VERSION 5.7 ;
  NOWIREEXTENSIONATPIN ON ;
  DIVIDERCHAR "/" ;
  BUSBITCHARS "[]" ;
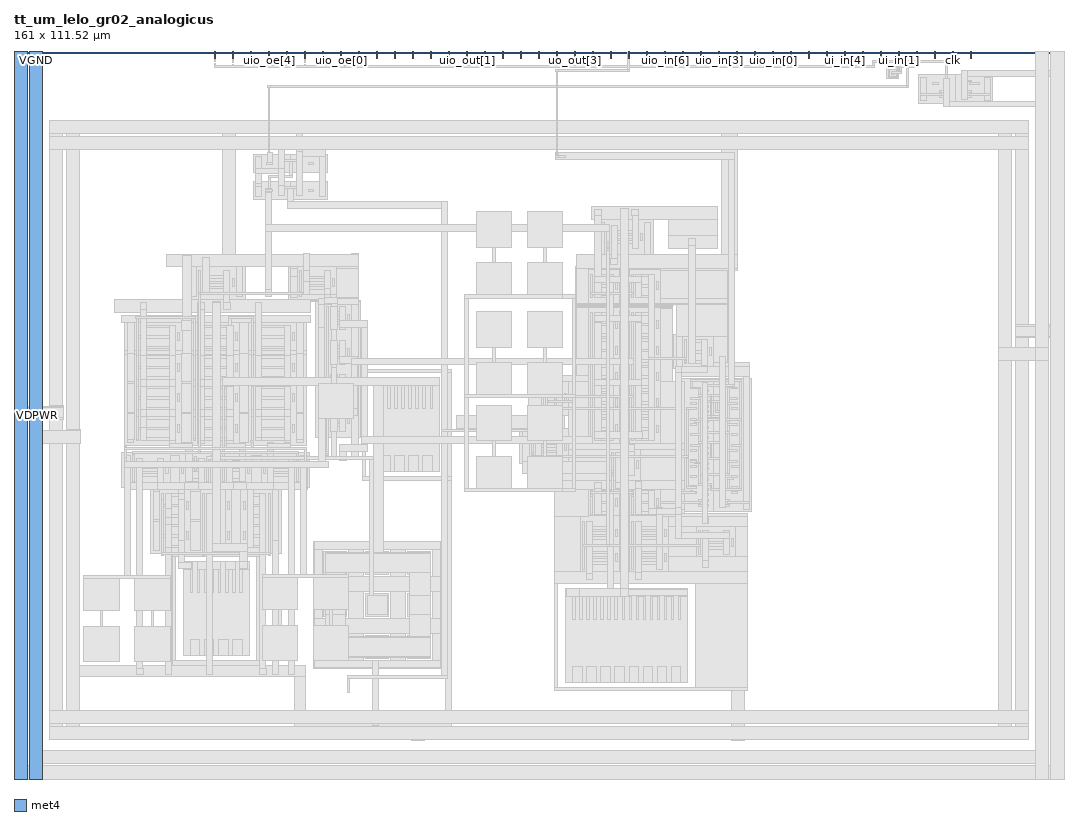
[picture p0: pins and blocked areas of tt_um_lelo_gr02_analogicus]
MACRO tt_um_lelo_gr02_analogicus
  CLASS BLOCK ;
  FOREIGN tt_um_lelo_gr02_analogicus ;
  ORIGIN 0.000 0.000 ;
  SIZE 161.000 BY 111.520 ;
  PIN uo_out[7]
    DIRECTION OUTPUT ;
    USE SIGNAL ;
    PORT
      LAYER met4 ;
        RECT 74.830 110.520 75.130 111.520 ;
    END
  END uo_out[7]
  PIN uo_out[6]
    DIRECTION OUTPUT ;
    USE SIGNAL ;
    PORT
      LAYER met4 ;
        RECT 77.590 110.520 77.890 111.520 ;
    END
  END uo_out[6]
  PIN uo_out[5]
    DIRECTION OUTPUT ;
    USE SIGNAL ;
    PORT
      LAYER met4 ;
        RECT 80.350 110.520 80.650 111.520 ;
    END
  END uo_out[5]
  PIN uo_out[4]
    DIRECTION OUTPUT ;
    USE SIGNAL ;
    PORT
      LAYER met4 ;
        RECT 83.110 110.520 83.410 111.520 ;
    END
  END uo_out[4]
  PIN uo_out[3]
    DIRECTION OUTPUT ;
    USE SIGNAL ;
    PORT
      LAYER met4 ;
        RECT 85.870 110.520 86.170 111.520 ;
    END
  END uo_out[3]
  PIN uo_out[2]
    DIRECTION OUTPUT ;
    USE SIGNAL ;
    PORT
      LAYER met4 ;
        RECT 88.630 110.520 88.930 111.520 ;
    END
  END uo_out[2]
  PIN uo_out[1]
    DIRECTION OUTPUT ;
    USE SIGNAL ;
    PORT
      LAYER met4 ;
        RECT 91.390 110.520 91.690 111.520 ;
    END
  END uo_out[1]
  PIN uo_out[0]
    DIRECTION OUTPUT ;
    USE SIGNAL ;
    ANTENNAGATEAREA 0.288000 ;
    ANTENNADIFFAREA 0.936000 ;
    PORT
      LAYER met4 ;
        RECT 94.150 110.520 94.450 111.520 ;
    END
  END uo_out[0]
  PIN uio_out[7]
    DIRECTION OUTPUT ;
    USE SIGNAL ;
    PORT
      LAYER met4 ;
        RECT 52.750 110.520 53.050 111.520 ;
    END
  END uio_out[7]
  PIN uio_out[6]
    DIRECTION OUTPUT ;
    USE SIGNAL ;
    PORT
      LAYER met4 ;
        RECT 55.510 110.520 55.810 111.520 ;
    END
  END uio_out[6]
  PIN uio_out[5]
    DIRECTION OUTPUT ;
    USE SIGNAL ;
    PORT
      LAYER met4 ;
        RECT 58.270 110.520 58.570 111.520 ;
    END
  END uio_out[5]
  PIN uio_out[4]
    DIRECTION OUTPUT ;
    USE SIGNAL ;
    PORT
      LAYER met4 ;
        RECT 61.030 110.520 61.330 111.520 ;
    END
  END uio_out[4]
  PIN uio_out[3]
    DIRECTION OUTPUT ;
    USE SIGNAL ;
    PORT
      LAYER met4 ;
        RECT 63.790 110.520 64.090 111.520 ;
    END
  END uio_out[3]
  PIN uio_out[2]
    DIRECTION OUTPUT ;
    USE SIGNAL ;
    PORT
      LAYER met4 ;
        RECT 66.550 110.520 66.850 111.520 ;
    END
  END uio_out[2]
  PIN uio_out[1]
    DIRECTION OUTPUT ;
    USE SIGNAL ;
    PORT
      LAYER met4 ;
        RECT 69.310 110.520 69.610 111.520 ;
    END
  END uio_out[1]
  PIN uio_out[0]
    DIRECTION OUTPUT ;
    USE SIGNAL ;
    PORT
      LAYER met4 ;
        RECT 72.070 110.520 72.370 111.520 ;
    END
  END uio_out[0]
  PIN uio_oe[7]
    DIRECTION OUTPUT ;
    USE SIGNAL ;
    PORT
      LAYER met4 ;
        RECT 30.670 110.520 30.970 111.520 ;
    END
  END uio_oe[7]
  PIN uio_oe[6]
    DIRECTION OUTPUT ;
    USE SIGNAL ;
    PORT
      LAYER met4 ;
        RECT 33.430 110.520 33.730 111.520 ;
    END
  END uio_oe[6]
  PIN uio_oe[5]
    DIRECTION OUTPUT ;
    USE SIGNAL ;
    PORT
      LAYER met4 ;
        RECT 36.190 110.520 36.490 111.520 ;
    END
  END uio_oe[5]
  PIN uio_oe[4]
    DIRECTION OUTPUT ;
    USE SIGNAL ;
    PORT
      LAYER met4 ;
        RECT 38.950 110.520 39.250 111.520 ;
    END
  END uio_oe[4]
  PIN uio_oe[3]
    DIRECTION OUTPUT ;
    USE SIGNAL ;
    PORT
      LAYER met4 ;
        RECT 41.710 110.520 42.010 111.520 ;
    END
  END uio_oe[3]
  PIN uio_oe[2]
    DIRECTION OUTPUT ;
    USE SIGNAL ;
    PORT
      LAYER met4 ;
        RECT 44.470 110.520 44.770 111.520 ;
    END
  END uio_oe[2]
  PIN uio_oe[1]
    DIRECTION OUTPUT ;
    USE SIGNAL ;
    PORT
      LAYER met4 ;
        RECT 47.230 110.520 47.530 111.520 ;
    END
  END uio_oe[1]
  PIN uio_oe[0]
    DIRECTION OUTPUT ;
    USE SIGNAL ;
    PORT
      LAYER met4 ;
        RECT 49.990 110.520 50.290 111.520 ;
    END
  END uio_oe[0]
  PIN VDPWR
    DIRECTION INOUT ;
    USE POWER ;
    PORT
      LAYER met4 ;
        RECT 0.000 0.000 2.000 111.520 ;
    END
  END VDPWR
  PIN VGND
    DIRECTION INOUT ;
    USE GROUND ;
    PORT
      LAYER met4 ;
        RECT 2.400 0.000 4.400 111.520 ;
    END
  END VGND
  PIN ui_in[7]
    DIRECTION INPUT ;
    USE SIGNAL ;
    PORT
      LAYER met4 ;
        RECT 118.990 110.520 119.290 111.520 ;
    END
  END ui_in[7]
  PIN ui_in[6]
    DIRECTION INPUT ;
    USE SIGNAL ;
    PORT
      LAYER met4 ;
        RECT 121.750 110.520 122.050 111.520 ;
    END
  END ui_in[6]
  PIN ui_in[5]
    DIRECTION INPUT ;
    USE SIGNAL ;
    PORT
      LAYER met4 ;
        RECT 124.510 110.520 124.810 111.520 ;
    END
  END ui_in[5]
  PIN ui_in[4]
    DIRECTION INPUT ;
    USE SIGNAL ;
    PORT
      LAYER met4 ;
        RECT 127.270 110.520 127.570 111.520 ;
    END
  END ui_in[4]
  PIN ui_in[3]
    DIRECTION INPUT ;
    USE SIGNAL ;
    PORT
      LAYER met4 ;
        RECT 130.030 110.520 130.330 111.520 ;
    END
  END ui_in[3]
  PIN ui_in[2]
    DIRECTION INPUT ;
    USE SIGNAL ;
    PORT
      LAYER met4 ;
        RECT 132.790 110.520 133.090 111.520 ;
    END
  END ui_in[2]
  PIN ui_in[1]
    DIRECTION INPUT ;
    USE SIGNAL ;
    PORT
      LAYER met4 ;
        RECT 135.550 110.520 135.850 111.520 ;
    END
  END ui_in[1]
  PIN ui_in[0]
    DIRECTION INPUT ;
    USE SIGNAL ;
    ANTENNAGATEAREA 0.490500 ;
    ANTENNADIFFAREA 0.202500 ;
    PORT
      LAYER met4 ;
        RECT 138.310 110.520 138.610 111.520 ;
    END
  END ui_in[0]
  PIN uio_in[7]
    DIRECTION INPUT ;
    USE SIGNAL ;
    PORT
      LAYER met4 ;
        RECT 96.910 110.520 97.210 111.520 ;
    END
  END uio_in[7]
  PIN uio_in[6]
    DIRECTION INPUT ;
    USE SIGNAL ;
    PORT
      LAYER met4 ;
        RECT 99.670 110.520 99.970 111.520 ;
    END
  END uio_in[6]
  PIN uio_in[5]
    DIRECTION INPUT ;
    USE SIGNAL ;
    PORT
      LAYER met4 ;
        RECT 102.430 110.520 102.730 111.520 ;
    END
  END uio_in[5]
  PIN uio_in[4]
    DIRECTION INPUT ;
    USE SIGNAL ;
    PORT
      LAYER met4 ;
        RECT 105.190 110.520 105.490 111.520 ;
    END
  END uio_in[4]
  PIN uio_in[3]
    DIRECTION INPUT ;
    USE SIGNAL ;
    PORT
      LAYER met4 ;
        RECT 107.950 110.520 108.250 111.520 ;
    END
  END uio_in[3]
  PIN uio_in[2]
    DIRECTION INPUT ;
    USE SIGNAL ;
    PORT
      LAYER met4 ;
        RECT 110.710 110.520 111.010 111.520 ;
    END
  END uio_in[2]
  PIN uio_in[1]
    DIRECTION INPUT ;
    USE SIGNAL ;
    PORT
      LAYER met4 ;
        RECT 113.470 110.520 113.770 111.520 ;
    END
  END uio_in[1]
  PIN uio_in[0]
    DIRECTION INPUT ;
    USE SIGNAL ;
    PORT
      LAYER met4 ;
        RECT 116.230 110.520 116.530 111.520 ;
    END
  END uio_in[0]
  PIN ena
    DIRECTION INPUT ;
    USE SIGNAL ;
    PORT
      LAYER met4 ;
        RECT 146.590 110.520 146.890 111.520 ;
    END
  END ena
  PIN rst_n
    DIRECTION INPUT ;
    USE SIGNAL ;
    PORT
      LAYER met4 ;
        RECT 141.070 110.520 141.370 111.520 ;
    END
  END rst_n
  PIN clk
    DIRECTION INPUT ;
    USE SIGNAL ;
    PORT
      LAYER met4 ;
        RECT 143.830 110.520 144.130 111.520 ;
    END
  END clk
  OBS
      LAYER pwell ;
        RECT 133.855 107.375 135.685 109.205 ;
        RECT 138.680 103.630 144.380 108.030 ;
      LAYER nwell ;
        RECT 144.380 103.630 150.080 108.030 ;
      LAYER pwell ;
        RECT 36.690 93.010 42.390 95.810 ;
      LAYER nwell ;
        RECT 42.390 93.010 48.090 95.810 ;
      LAYER pwell ;
        RECT 36.690 88.860 42.390 91.660 ;
      LAYER nwell ;
        RECT 42.390 88.860 48.090 91.660 ;
        RECT 89.205 80.475 98.085 85.755 ;
        RECT 26.600 73.520 35.480 78.800 ;
        RECT 42.020 74.295 50.900 78.740 ;
        RECT 86.130 78.105 101.155 78.625 ;
        RECT 42.020 73.460 50.910 74.295 ;
        RECT 42.025 73.320 50.910 73.460 ;
        RECT 42.025 73.240 53.190 73.320 ;
        RECT 17.000 65.750 44.785 70.430 ;
        RECT 16.995 65.150 44.785 65.750 ;
        RECT 16.995 51.130 44.780 65.150 ;
        RECT 46.230 52.395 53.190 73.240 ;
        RECT 86.130 72.575 101.165 78.105 ;
        RECT 86.130 72.570 101.155 72.575 ;
      LAYER pwell ;
        RECT 86.690 72.320 94.290 72.325 ;
        RECT 23.985 50.045 37.840 50.050 ;
        RECT 16.455 50.040 37.840 50.045 ;
        RECT 16.455 44.770 45.370 50.040 ;
        RECT 55.150 47.140 65.230 61.540 ;
        RECT 79.505 55.795 86.465 61.075 ;
        RECT 77.585 48.400 86.465 53.680 ;
        RECT 86.690 51.045 100.540 72.320 ;
      LAYER nwell ;
        RECT 101.115 62.875 108.715 68.155 ;
      LAYER pwell ;
        RECT 92.940 51.040 100.540 51.045 ;
        RECT 89.895 45.645 97.495 50.925 ;
        RECT 16.455 44.765 25.335 44.770 ;
        RECT 36.490 44.760 45.370 44.770 ;
        RECT 27.145 44.595 34.745 44.600 ;
        RECT 20.885 34.645 40.995 44.595 ;
        RECT 86.690 40.360 100.540 45.030 ;
        RECT 101.625 40.955 107.325 61.355 ;
      LAYER nwell ;
        RECT 107.325 40.955 113.025 61.355 ;
      LAYER pwell ;
        RECT 20.885 34.640 28.485 34.645 ;
        RECT 33.395 34.640 40.995 34.645 ;
        RECT 45.900 35.705 65.480 36.470 ;
        RECT 25.975 18.950 36.055 33.350 ;
        RECT 45.900 30.535 46.665 35.705 ;
        RECT 51.835 30.535 53.105 35.705 ;
        RECT 58.275 30.535 59.545 35.705 ;
        RECT 64.715 30.535 65.480 35.705 ;
        RECT 85.410 31.300 101.820 40.360 ;
        RECT 103.200 33.605 112.080 38.885 ;
        RECT 45.900 29.265 65.480 30.535 ;
        RECT 45.900 24.095 46.665 29.265 ;
        RECT 51.835 24.095 53.105 29.265 ;
        RECT 58.275 24.095 59.545 29.265 ;
        RECT 64.715 24.095 65.480 29.265 ;
        RECT 45.900 22.825 65.480 24.095 ;
        RECT 45.900 17.655 46.665 22.825 ;
        RECT 51.835 17.655 53.105 22.825 ;
        RECT 58.275 17.655 59.545 22.825 ;
        RECT 64.715 17.655 65.480 22.825 ;
        RECT 45.900 16.890 65.480 17.655 ;
        RECT 84.590 14.830 103.310 29.230 ;
      LAYER li1 ;
        RECT 134.035 108.855 135.505 109.025 ;
        RECT 134.035 107.725 134.205 108.855 ;
        RECT 134.525 108.125 135.015 108.455 ;
        RECT 135.335 107.725 135.505 108.855 ;
        RECT 134.035 107.555 135.505 107.725 ;
        RECT 138.980 105.180 139.880 107.630 ;
        RECT 142.790 107.180 143.090 108.350 ;
        RECT 142.580 106.880 143.480 107.180 ;
        RECT 145.280 106.880 146.780 107.180 ;
        RECT 146.480 106.780 146.780 106.880 ;
        RECT 140.780 106.480 141.680 106.780 ;
        RECT 146.480 106.480 147.980 106.780 ;
        RECT 142.580 106.380 143.420 106.400 ;
        RECT 145.280 106.380 146.120 106.400 ;
        RECT 142.580 106.080 143.480 106.380 ;
        RECT 145.280 106.080 146.180 106.380 ;
        RECT 142.580 105.580 143.420 105.600 ;
        RECT 145.280 105.580 146.120 105.600 ;
        RECT 141.980 105.280 143.480 105.580 ;
        RECT 145.280 105.280 146.780 105.580 ;
        RECT 141.980 105.180 142.280 105.280 ;
        RECT 138.980 104.880 142.280 105.180 ;
        RECT 138.980 104.030 139.880 104.880 ;
        RECT 141.980 104.780 142.280 104.880 ;
        RECT 146.480 105.180 146.780 105.280 ;
        RECT 148.880 105.180 149.780 107.630 ;
        RECT 146.480 104.880 149.780 105.180 ;
        RECT 142.580 104.780 143.420 104.800 ;
        RECT 145.280 104.780 146.120 104.800 ;
        RECT 146.480 104.780 146.780 104.880 ;
        RECT 141.980 104.480 143.480 104.780 ;
        RECT 145.280 104.480 146.780 104.780 ;
        RECT 148.880 104.030 149.780 104.880 ;
        RECT 32.000 80.500 34.000 101.000 ;
        RECT 46.890 96.500 47.795 96.505 ;
        RECT 38.805 95.570 39.685 96.005 ;
        RECT 36.990 93.600 37.890 95.410 ;
        RECT 38.795 94.560 39.690 95.570 ;
        RECT 43.290 95.500 47.795 96.500 ;
        RECT 43.290 95.490 44.170 95.500 ;
        RECT 46.890 95.410 47.795 95.500 ;
        RECT 42.280 94.960 42.650 94.995 ;
        RECT 40.590 94.660 44.190 94.960 ;
        RECT 38.790 94.260 39.690 94.560 ;
        RECT 40.590 94.160 41.430 94.180 ;
        RECT 40.590 93.860 41.490 94.160 ;
        RECT 36.990 92.800 41.400 93.600 ;
        RECT 36.990 91.260 37.890 92.800 ;
        RECT 42.280 92.610 42.650 94.660 ;
        RECT 45.090 94.260 45.990 94.560 ;
        RECT 43.290 94.160 44.130 94.180 ;
        RECT 43.290 93.860 44.190 94.160 ;
        RECT 38.965 92.240 42.650 92.610 ;
        RECT 36.990 90.870 37.905 91.260 ;
        RECT 36.990 90.860 37.900 90.870 ;
        RECT 36.990 89.260 37.890 90.860 ;
        RECT 38.965 90.500 39.335 92.240 ;
        RECT 40.590 90.510 44.190 90.810 ;
        RECT 38.500 90.410 39.500 90.500 ;
        RECT 38.500 90.110 39.690 90.410 ;
        RECT 38.500 89.000 39.500 90.110 ;
        RECT 40.590 90.010 41.430 90.030 ;
        RECT 40.590 89.710 41.490 90.010 ;
        RECT 41.900 88.500 42.900 90.510 ;
        RECT 45.090 90.110 45.990 90.410 ;
        RECT 43.290 90.010 44.130 90.030 ;
        RECT 43.290 89.710 44.190 90.010 ;
        RECT 46.890 89.260 47.790 95.410 ;
        RECT 41.900 87.500 66.500 88.500 ;
        RECT 88.610 85.840 107.900 87.840 ;
        RECT 51.790 80.500 52.750 80.520 ;
        RECT 23.440 78.540 52.750 80.500 ;
        RECT 89.645 80.400 90.605 85.315 ;
        RECT 91.565 83.715 95.085 84.115 ;
        RECT 90.925 82.515 91.245 83.715 ;
        RECT 92.205 82.915 95.725 83.315 ;
        RECT 96.045 82.515 96.365 83.715 ;
        RECT 91.565 82.115 95.085 82.515 ;
        RECT 96.685 80.400 97.645 85.315 ;
        RECT 100.400 83.330 107.900 85.840 ;
        RECT 100.400 81.330 107.915 83.330 ;
        RECT 101.555 80.400 108.275 80.405 ;
        RECT 108.500 80.400 111.000 101.000 ;
        RECT 27.040 73.960 28.000 78.540 ;
        RECT 28.960 76.760 32.480 77.160 ;
        RECT 28.320 75.560 28.640 76.760 ;
        RECT 29.600 75.960 33.120 76.360 ;
        RECT 33.440 75.560 33.760 76.760 ;
        RECT 28.960 75.160 32.480 75.560 ;
        RECT 34.080 73.960 35.040 78.540 ;
        RECT 42.465 78.300 43.425 78.540 ;
        RECT 49.505 78.300 52.750 78.540 ;
        RECT 42.460 77.095 43.425 78.300 ;
        RECT 42.460 73.900 43.420 77.095 ;
        RECT 44.380 76.700 47.900 77.100 ;
        RECT 43.740 75.500 44.060 76.700 ;
        RECT 45.020 75.900 48.540 76.300 ;
        RECT 48.860 75.500 49.180 76.700 ;
        RECT 44.380 75.100 47.900 75.500 ;
        RECT 49.500 73.900 52.750 78.300 ;
        RECT 49.505 73.730 52.750 73.900 ;
        RECT 86.310 78.275 111.000 80.400 ;
        RECT 15.430 71.540 45.410 73.520 ;
        RECT 46.670 72.770 52.760 73.730 ;
        RECT 86.310 72.920 88.090 78.275 ;
        RECT 89.050 77.010 91.290 77.410 ;
        RECT 88.410 75.010 88.730 76.210 ;
        RECT 89.690 75.410 91.930 75.810 ;
        RECT 92.250 75.010 92.570 76.210 ;
        RECT 89.050 73.810 91.290 74.210 ;
        RECT 92.890 72.920 94.340 78.275 ;
        RECT 99.140 78.000 111.000 78.275 ;
        RECT 95.300 77.010 97.540 77.410 ;
        RECT 94.660 75.010 94.980 76.210 ;
        RECT 95.940 75.410 98.180 75.810 ;
        RECT 98.500 75.010 98.820 76.210 ;
        RECT 95.300 73.810 97.540 74.210 ;
        RECT 99.140 73.745 109.400 78.000 ;
        RECT 99.125 72.920 109.400 73.745 ;
        RECT 16.440 70.040 45.400 71.000 ;
        RECT 17.440 65.310 18.400 70.040 ;
        RECT 19.360 69.190 24.160 69.590 ;
        RECT 18.720 67.980 19.040 68.390 ;
        RECT 20.000 67.980 24.800 67.990 ;
        RECT 18.720 67.590 24.800 67.980 ;
        RECT 18.720 67.580 20.720 67.590 ;
        RECT 18.720 67.190 19.040 67.580 ;
        RECT 25.120 67.190 25.440 68.390 ;
        RECT 19.360 65.990 24.160 66.390 ;
        RECT 25.760 65.310 27.215 70.040 ;
        RECT 28.175 69.190 32.975 69.590 ;
        RECT 27.535 67.190 27.855 68.390 ;
        RECT 28.815 67.590 33.615 67.990 ;
        RECT 33.935 67.190 34.255 68.390 ;
        RECT 28.175 65.990 32.975 66.390 ;
        RECT 34.575 65.310 36.025 70.040 ;
        RECT 36.985 69.190 41.785 69.590 ;
        RECT 36.345 67.190 36.665 68.390 ;
        RECT 37.625 67.590 42.425 67.990 ;
        RECT 42.745 67.190 43.065 68.390 ;
        RECT 36.985 65.990 41.785 66.390 ;
        RECT 43.385 65.310 44.345 70.040 ;
        RECT 46.670 69.170 47.630 72.770 ;
        RECT 48.590 71.280 50.190 71.680 ;
        RECT 47.950 70.080 48.270 71.280 ;
        RECT 49.230 70.480 50.830 70.880 ;
        RECT 51.150 70.080 51.470 71.280 ;
        RECT 48.590 69.680 50.190 70.080 ;
        RECT 17.435 60.910 18.400 65.310 ;
        RECT 19.355 64.510 24.155 64.910 ;
        RECT 18.715 63.310 19.035 63.710 ;
        RECT 18.715 62.910 24.795 63.310 ;
        RECT 18.715 62.510 19.035 62.910 ;
        RECT 25.115 62.510 25.435 63.710 ;
        RECT 19.355 61.310 24.155 61.710 ;
        RECT 25.755 60.910 27.215 65.310 ;
        RECT 28.170 64.510 32.970 64.910 ;
        RECT 27.530 62.510 27.850 63.710 ;
        RECT 28.810 62.910 33.610 63.310 ;
        RECT 33.930 62.510 34.250 63.710 ;
        RECT 28.170 61.310 32.970 61.710 ;
        RECT 34.570 60.910 36.025 65.310 ;
        RECT 36.980 64.510 41.780 64.910 ;
        RECT 36.340 62.510 36.660 63.710 ;
        RECT 37.620 62.910 42.420 63.310 ;
        RECT 42.740 62.510 43.060 63.710 ;
        RECT 36.980 61.310 41.780 61.710 ;
        RECT 43.380 60.910 44.345 65.310 ;
        RECT 17.440 60.640 18.400 60.910 ;
        RECT 25.760 60.640 27.215 60.910 ;
        RECT 34.575 60.640 36.025 60.910 ;
        RECT 43.385 60.640 44.345 60.910 ;
        RECT 17.435 56.240 18.400 60.640 ;
        RECT 19.355 59.840 24.155 60.240 ;
        RECT 18.715 58.640 19.035 59.040 ;
        RECT 18.715 58.240 24.795 58.640 ;
        RECT 18.715 57.840 19.035 58.240 ;
        RECT 25.115 57.840 25.435 59.040 ;
        RECT 19.355 56.640 24.155 57.040 ;
        RECT 25.755 56.240 27.215 60.640 ;
        RECT 28.170 59.840 32.970 60.240 ;
        RECT 27.530 57.840 27.850 59.040 ;
        RECT 28.810 58.240 33.610 58.640 ;
        RECT 33.930 57.840 34.250 59.040 ;
        RECT 28.170 56.640 32.970 57.040 ;
        RECT 34.570 56.240 36.025 60.640 ;
        RECT 36.980 59.840 41.780 60.240 ;
        RECT 36.340 57.840 36.660 59.040 ;
        RECT 37.620 58.240 42.420 58.640 ;
        RECT 42.740 57.840 43.060 59.040 ;
        RECT 36.980 56.640 41.780 57.040 ;
        RECT 43.380 56.240 44.345 60.640 ;
        RECT 17.440 55.970 18.400 56.240 ;
        RECT 25.760 55.970 27.215 56.240 ;
        RECT 34.575 55.970 36.025 56.240 ;
        RECT 43.385 55.970 44.345 56.240 ;
        RECT 17.435 52.020 18.400 55.970 ;
        RECT 19.355 55.170 24.155 55.570 ;
        RECT 18.715 53.970 19.035 54.370 ;
        RECT 18.715 53.570 24.795 53.970 ;
        RECT 18.715 53.170 19.035 53.570 ;
        RECT 25.115 53.170 25.435 54.370 ;
        RECT 17.435 51.570 18.395 52.020 ;
        RECT 19.355 51.970 24.155 52.370 ;
        RECT 25.755 51.570 27.215 55.970 ;
        RECT 28.170 55.170 32.970 55.570 ;
        RECT 27.530 53.170 27.850 54.370 ;
        RECT 28.810 53.570 33.610 53.970 ;
        RECT 33.930 53.170 34.250 54.370 ;
        RECT 28.170 51.970 32.970 52.370 ;
        RECT 34.570 51.570 36.025 55.970 ;
        RECT 36.980 55.170 41.780 55.570 ;
        RECT 36.340 53.170 36.660 54.370 ;
        RECT 37.620 53.570 42.420 53.970 ;
        RECT 42.740 53.170 43.060 54.370 ;
        RECT 36.980 51.970 41.780 52.370 ;
        RECT 43.380 52.020 44.345 55.970 ;
        RECT 46.660 54.765 47.645 69.170 ;
        RECT 48.590 66.015 50.190 66.415 ;
        RECT 47.950 64.815 48.270 66.015 ;
        RECT 49.230 65.215 50.830 65.615 ;
        RECT 51.150 64.815 51.470 66.015 ;
        RECT 48.590 64.415 50.190 64.815 ;
        RECT 48.590 60.820 50.190 61.220 ;
        RECT 47.950 59.620 48.270 60.820 ;
        RECT 49.230 60.020 50.830 60.420 ;
        RECT 51.150 59.620 51.470 60.820 ;
        RECT 48.590 59.220 50.190 59.620 ;
        RECT 48.590 55.635 50.190 56.035 ;
        RECT 43.380 51.570 44.340 52.020 ;
        RECT 24.425 49.605 25.385 49.610 ;
        RECT 16.895 45.400 17.870 49.605 ;
        RECT 18.815 48.005 22.335 48.405 ;
        RECT 18.175 46.805 18.495 48.005 ;
        RECT 19.455 47.205 22.975 47.605 ;
        RECT 23.295 46.805 23.615 48.005 ;
        RECT 18.815 46.405 22.335 46.805 ;
        RECT 23.935 45.400 25.385 49.605 ;
        RECT 26.985 48.810 29.225 49.210 ;
        RECT 25.705 46.810 26.025 48.010 ;
        RECT 26.345 47.210 28.585 47.610 ;
        RECT 29.545 46.810 29.865 48.010 ;
        RECT 26.985 45.610 29.225 46.010 ;
        RECT 30.185 45.400 31.640 49.610 ;
        RECT 36.440 49.600 37.400 49.610 ;
        RECT 32.600 48.810 34.840 49.210 ;
        RECT 31.960 46.810 32.280 48.010 ;
        RECT 33.240 47.210 35.480 47.610 ;
        RECT 35.800 46.810 36.120 48.010 ;
        RECT 32.600 45.610 34.840 46.010 ;
        RECT 36.440 45.400 37.890 49.600 ;
        RECT 39.490 48.000 43.010 48.400 ;
        RECT 38.210 46.800 38.530 48.000 ;
        RECT 38.850 47.200 42.370 47.600 ;
        RECT 43.330 46.800 43.650 48.000 ;
        RECT 39.490 46.400 43.010 46.800 ;
        RECT 43.970 45.400 44.930 49.600 ;
        RECT 46.670 49.255 47.630 54.765 ;
        RECT 47.950 54.435 48.270 55.635 ;
        RECT 49.230 54.835 50.830 55.235 ;
        RECT 51.150 54.435 51.470 55.635 ;
        RECT 48.590 54.035 50.190 54.435 ;
        RECT 51.790 49.255 52.750 72.770 ;
        RECT 86.310 72.750 109.400 72.920 ;
        RECT 86.315 72.255 100.985 72.425 ;
        RECT 53.410 62.840 66.970 62.860 ;
        RECT 53.410 62.300 67.030 62.840 ;
        RECT 53.410 46.380 53.970 62.300 ;
        RECT 55.150 60.340 56.590 61.540 ;
        RECT 56.230 56.740 56.590 60.340 ;
        RECT 57.310 60.340 58.750 61.540 ;
        RECT 57.310 56.740 57.670 60.340 ;
        RECT 58.390 56.740 58.750 60.340 ;
        RECT 59.470 60.340 60.910 61.540 ;
        RECT 59.470 56.740 59.830 60.340 ;
        RECT 60.550 56.740 60.910 60.340 ;
        RECT 61.630 60.340 63.070 61.540 ;
        RECT 61.630 56.740 61.990 60.340 ;
        RECT 62.710 56.740 63.070 60.340 ;
        RECT 63.790 60.340 65.230 61.540 ;
        RECT 63.790 56.740 64.150 60.340 ;
        RECT 56.230 47.140 57.670 49.540 ;
        RECT 58.390 47.140 59.830 49.540 ;
        RECT 60.550 47.140 61.990 49.540 ;
        RECT 62.710 47.140 64.150 49.540 ;
        RECT 66.230 46.380 67.030 62.300 ;
        RECT 86.315 61.855 88.090 72.255 ;
        RECT 99.135 72.125 100.985 72.255 ;
        RECT 92.890 71.880 93.850 71.885 ;
        RECT 89.050 71.085 91.290 71.485 ;
        RECT 88.410 69.085 88.730 70.285 ;
        RECT 89.690 69.485 91.930 69.885 ;
        RECT 92.250 69.085 92.570 70.285 ;
        RECT 89.050 67.885 91.290 68.285 ;
        RECT 89.050 67.085 91.290 67.485 ;
        RECT 88.410 65.085 88.730 66.285 ;
        RECT 89.690 65.485 91.930 65.885 ;
        RECT 92.250 65.085 92.570 66.285 ;
        RECT 89.050 63.885 91.290 64.285 ;
        RECT 89.050 63.085 91.290 63.485 ;
        RECT 78.915 60.890 88.090 61.855 ;
        RECT 88.410 61.085 88.730 62.285 ;
        RECT 89.690 61.485 91.930 61.885 ;
        RECT 92.250 61.085 92.570 62.285 ;
        RECT 78.915 56.260 80.905 60.890 ;
        RECT 81.865 59.835 83.465 60.235 ;
        RECT 81.225 57.835 81.545 59.035 ;
        RECT 82.505 58.235 84.105 58.635 ;
        RECT 84.425 57.835 84.745 59.035 ;
        RECT 81.865 56.635 83.465 57.035 ;
        RECT 79.945 56.235 80.905 56.260 ;
        RECT 67.900 53.740 84.400 55.740 ;
        RECT 78.025 48.735 78.985 53.240 ;
        RECT 79.945 51.640 83.465 52.040 ;
        RECT 79.305 50.440 79.625 51.640 ;
        RECT 80.585 50.840 84.105 51.240 ;
        RECT 84.425 50.440 84.745 51.640 ;
        RECT 85.065 51.435 88.090 60.890 ;
        RECT 89.050 59.885 91.290 60.285 ;
        RECT 89.050 59.085 91.290 59.485 ;
        RECT 88.410 57.085 88.730 58.285 ;
        RECT 89.690 57.485 91.930 57.885 ;
        RECT 92.250 57.085 92.570 58.285 ;
        RECT 89.050 55.885 91.290 56.285 ;
        RECT 89.050 55.085 91.290 55.485 ;
        RECT 88.410 53.085 88.730 54.285 ;
        RECT 89.690 53.485 91.930 53.885 ;
        RECT 92.250 53.085 92.570 54.285 ;
        RECT 89.050 51.885 91.290 52.285 ;
        RECT 92.890 51.435 94.340 71.880 ;
        RECT 95.300 71.080 97.540 71.480 ;
        RECT 94.660 69.080 94.980 70.280 ;
        RECT 95.940 69.480 98.180 69.880 ;
        RECT 98.500 69.080 98.820 70.280 ;
        RECT 95.300 67.880 97.540 68.280 ;
        RECT 95.300 67.080 97.540 67.480 ;
        RECT 94.660 65.080 94.980 66.280 ;
        RECT 95.940 65.480 98.180 65.880 ;
        RECT 98.500 65.080 98.820 66.280 ;
        RECT 95.300 63.880 97.540 64.280 ;
        RECT 95.300 63.080 97.540 63.480 ;
        RECT 94.660 61.080 94.980 62.280 ;
        RECT 95.940 61.480 98.180 61.880 ;
        RECT 98.500 61.080 98.820 62.280 ;
        RECT 99.140 60.955 100.985 72.125 ;
        RECT 101.555 67.860 109.400 72.750 ;
        RECT 101.555 63.280 102.515 67.860 ;
        RECT 103.475 66.915 105.715 67.315 ;
        RECT 102.835 64.915 103.155 66.115 ;
        RECT 104.115 65.315 106.355 65.715 ;
        RECT 106.675 64.915 106.995 66.115 ;
        RECT 103.475 63.715 105.715 64.115 ;
        RECT 107.315 63.820 109.400 67.860 ;
        RECT 107.315 63.280 112.730 63.820 ;
        RECT 101.555 61.735 112.730 63.280 ;
        RECT 103.725 60.955 111.515 61.255 ;
        RECT 95.300 59.880 97.540 60.280 ;
        RECT 95.300 59.080 97.540 59.480 ;
        RECT 94.660 57.080 94.980 58.280 ;
        RECT 95.940 57.480 98.180 57.880 ;
        RECT 98.500 57.080 98.820 58.280 ;
        RECT 95.300 55.880 97.540 56.280 ;
        RECT 95.300 55.080 97.540 55.480 ;
        RECT 94.660 53.080 94.980 54.280 ;
        RECT 95.940 53.480 98.180 53.880 ;
        RECT 98.500 53.080 98.820 54.280 ;
        RECT 95.300 51.880 97.540 52.280 ;
        RECT 99.140 51.435 102.825 60.955 ;
        RECT 103.725 60.105 104.025 60.955 ;
        RECT 108.225 60.505 109.065 60.525 ;
        RECT 105.525 60.205 109.125 60.505 ;
        RECT 103.725 59.805 105.225 60.105 ;
        RECT 110.025 59.805 110.925 60.105 ;
        RECT 104.925 58.905 105.225 59.805 ;
        RECT 105.525 59.705 106.365 59.725 ;
        RECT 108.225 59.705 109.065 59.725 ;
        RECT 105.525 59.405 106.425 59.705 ;
        RECT 108.225 59.405 109.125 59.705 ;
        RECT 105.525 58.905 106.365 58.925 ;
        RECT 104.925 58.605 109.125 58.905 ;
        RECT 103.725 58.505 104.565 58.525 ;
        RECT 103.725 58.205 104.625 58.505 ;
        RECT 109.425 58.205 110.925 58.505 ;
        RECT 105.525 57.805 109.125 58.105 ;
        RECT 103.725 57.405 104.625 57.705 ;
        RECT 105.525 57.005 106.425 57.305 ;
        RECT 103.725 56.905 104.565 56.925 ;
        RECT 103.725 56.605 104.625 56.905 ;
        RECT 105.525 56.505 106.365 56.525 ;
        RECT 107.625 56.505 107.925 57.805 ;
        RECT 108.225 57.305 109.065 57.325 ;
        RECT 108.225 57.005 109.125 57.305 ;
        RECT 105.525 56.205 106.425 56.505 ;
        RECT 107.625 56.205 109.125 56.505 ;
        RECT 105.525 55.705 106.365 55.725 ;
        RECT 105.525 55.405 109.125 55.705 ;
        RECT 103.725 55.005 104.625 55.305 ;
        RECT 104.325 54.705 105.225 55.005 ;
        RECT 103.725 54.205 104.625 54.505 ;
        RECT 103.725 52.905 104.565 52.925 ;
        RECT 103.725 52.605 104.625 52.905 ;
        RECT 85.065 50.475 102.825 51.435 ;
        RECT 104.925 51.305 105.225 54.705 ;
        RECT 105.525 54.605 106.425 54.905 ;
        RECT 108.225 54.605 109.125 54.905 ;
        RECT 105.525 54.105 106.365 54.125 ;
        RECT 108.225 54.105 109.065 54.125 ;
        RECT 105.525 53.805 106.425 54.105 ;
        RECT 108.225 53.805 109.125 54.105 ;
        RECT 108.225 53.305 109.065 53.325 ;
        RECT 105.525 53.005 109.125 53.305 ;
        RECT 105.525 52.505 106.365 52.525 ;
        RECT 108.225 52.505 109.065 52.525 ;
        RECT 105.525 52.205 106.425 52.505 ;
        RECT 108.225 52.205 109.125 52.505 ;
        RECT 105.525 51.705 106.365 51.725 ;
        RECT 105.525 51.405 109.125 51.705 ;
        RECT 103.725 51.005 105.225 51.305 ;
        RECT 79.945 50.040 83.465 50.440 ;
        RECT 85.065 48.735 91.295 50.475 ;
        RECT 92.255 49.685 94.495 50.085 ;
        RECT 78.025 46.900 91.295 48.735 ;
        RECT 91.615 47.685 91.935 48.885 ;
        RECT 92.895 48.085 95.135 48.485 ;
        RECT 95.455 47.685 95.775 48.885 ;
        RECT 53.410 45.820 67.030 46.380 ;
        RECT 16.895 44.425 44.935 45.400 ;
        RECT 16.895 44.420 17.855 44.425 ;
        RECT 21.330 44.155 22.290 44.425 ;
        RECT 27.090 44.155 28.545 44.425 ;
        RECT 21.325 39.755 22.290 44.155 ;
        RECT 23.245 43.355 25.485 43.755 ;
        RECT 22.605 42.155 22.925 42.555 ;
        RECT 22.605 41.755 26.125 42.155 ;
        RECT 22.605 41.355 22.925 41.755 ;
        RECT 26.445 41.355 26.765 42.555 ;
        RECT 23.245 40.155 25.485 40.555 ;
        RECT 27.085 39.755 28.545 44.155 ;
        RECT 29.505 43.360 31.745 43.760 ;
        RECT 28.865 41.360 29.185 42.560 ;
        RECT 30.145 41.760 32.385 42.160 ;
        RECT 32.705 41.360 33.025 42.560 ;
        RECT 29.505 40.160 31.745 40.560 ;
        RECT 21.330 39.480 22.290 39.755 ;
        RECT 27.090 39.480 28.545 39.755 ;
        RECT 21.325 35.080 22.290 39.480 ;
        RECT 23.245 38.680 25.485 39.080 ;
        RECT 22.605 37.485 22.925 37.880 ;
        RECT 22.605 37.480 24.205 37.485 ;
        RECT 22.605 37.085 26.125 37.480 ;
        RECT 22.605 36.680 22.925 37.085 ;
        RECT 23.885 37.080 26.125 37.085 ;
        RECT 26.445 36.680 26.765 37.880 ;
        RECT 23.245 35.480 25.485 35.880 ;
        RECT 27.085 35.085 28.545 39.480 ;
        RECT 29.505 38.685 31.745 39.085 ;
        RECT 28.865 36.685 29.185 37.885 ;
        RECT 30.145 37.085 32.385 37.485 ;
        RECT 32.705 36.685 33.025 37.885 ;
        RECT 29.505 35.485 31.745 35.885 ;
        RECT 27.085 35.080 28.045 35.085 ;
        RECT 21.330 35.040 22.290 35.080 ;
        RECT 33.345 35.075 34.795 44.425 ;
        RECT 36.395 43.355 38.635 43.755 ;
        RECT 35.115 41.355 35.435 42.555 ;
        RECT 35.755 41.755 37.995 42.155 ;
        RECT 38.955 41.355 39.275 42.555 ;
        RECT 36.395 40.155 38.635 40.555 ;
        RECT 36.395 38.680 38.635 39.080 ;
        RECT 35.115 36.680 35.435 37.880 ;
        RECT 35.755 37.080 37.995 37.480 ;
        RECT 38.955 36.680 39.275 37.880 ;
        RECT 36.395 35.480 38.635 35.880 ;
        RECT 39.595 35.080 40.555 44.425 ;
        RECT 46.000 36.360 47.200 36.390 ;
        RECT 46.000 35.160 65.410 36.360 ;
        RECT 24.235 34.110 37.795 34.670 ;
        RECT 24.235 18.190 24.795 34.110 ;
        RECT 25.975 32.150 27.415 33.350 ;
        RECT 27.055 28.550 27.415 32.150 ;
        RECT 28.135 32.150 29.575 33.350 ;
        RECT 28.135 28.550 28.495 32.150 ;
        RECT 29.215 28.550 29.575 32.150 ;
        RECT 30.295 32.150 31.735 33.350 ;
        RECT 30.295 28.550 30.655 32.150 ;
        RECT 31.375 28.550 31.735 32.150 ;
        RECT 32.455 32.150 33.895 33.350 ;
        RECT 32.455 28.550 32.815 32.150 ;
        RECT 33.535 28.550 33.895 32.150 ;
        RECT 34.615 32.150 36.055 33.350 ;
        RECT 34.615 28.550 34.975 32.150 ;
        RECT 27.055 18.950 28.495 21.350 ;
        RECT 29.215 18.950 30.655 21.350 ;
        RECT 31.375 18.950 32.815 21.350 ;
        RECT 33.535 18.950 34.975 21.350 ;
        RECT 37.235 18.190 37.795 34.110 ;
        RECT 8.000 17.395 10.000 17.400 ;
        RECT 24.235 17.395 37.795 18.190 ;
        RECT 46.000 31.120 47.230 35.160 ;
        RECT 47.515 31.385 50.985 34.855 ;
        RECT 51.280 31.120 53.660 35.160 ;
        RECT 53.955 31.385 57.425 34.855 ;
        RECT 57.700 31.120 60.085 35.160 ;
        RECT 60.395 31.385 63.865 34.855 ;
        RECT 64.150 31.120 65.370 35.160 ;
        RECT 46.000 28.725 65.370 31.120 ;
        RECT 46.000 24.670 47.230 28.725 ;
        RECT 47.515 24.945 50.985 28.415 ;
        RECT 51.280 24.670 53.660 28.725 ;
        RECT 53.955 24.945 57.425 28.415 ;
        RECT 57.700 24.670 60.085 28.725 ;
        RECT 60.395 24.945 63.865 28.415 ;
        RECT 64.150 24.670 65.370 28.725 ;
        RECT 46.000 22.285 65.370 24.670 ;
        RECT 46.000 18.240 47.230 22.285 ;
        RECT 47.515 18.505 50.985 21.975 ;
        RECT 51.280 18.240 53.660 22.285 ;
        RECT 53.955 18.505 57.425 21.975 ;
        RECT 57.700 18.240 60.085 22.285 ;
        RECT 60.395 18.505 63.865 21.975 ;
        RECT 64.150 18.240 65.370 22.285 ;
        RECT 8.000 15.730 44.710 17.395 ;
        RECT 46.000 17.040 65.410 18.240 ;
        RECT 46.000 17.020 65.350 17.040 ;
        RECT 46.000 16.990 47.200 17.020 ;
        RECT 43.045 8.575 44.710 15.730 ;
        RECT 66.230 8.575 67.030 45.820 ;
        RECT 82.850 45.820 91.295 46.900 ;
        RECT 92.255 46.485 94.495 46.885 ;
        RECT 96.095 45.820 102.825 50.475 ;
        RECT 103.725 50.205 104.625 50.505 ;
        RECT 103.725 48.905 104.565 48.925 ;
        RECT 103.725 48.605 104.625 48.905 ;
        RECT 103.725 47.805 104.625 48.105 ;
        RECT 104.925 46.905 105.225 51.005 ;
        RECT 105.525 50.605 106.425 50.905 ;
        RECT 105.525 50.105 106.365 50.125 ;
        RECT 105.525 49.805 106.425 50.105 ;
        RECT 106.725 49.305 107.025 51.405 ;
        RECT 108.225 50.605 109.125 50.905 ;
        RECT 108.225 50.105 109.065 50.125 ;
        RECT 108.225 49.805 109.125 50.105 ;
        RECT 105.525 49.005 109.125 49.305 ;
        RECT 109.425 48.905 109.725 58.205 ;
        RECT 110.025 57.705 110.865 57.725 ;
        RECT 110.025 57.405 110.925 57.705 ;
        RECT 110.025 56.605 110.925 56.905 ;
        RECT 110.025 55.305 110.865 55.325 ;
        RECT 110.025 55.005 110.925 55.305 ;
        RECT 110.025 54.505 110.865 54.525 ;
        RECT 110.025 54.205 110.925 54.505 ;
        RECT 110.025 52.605 110.925 52.905 ;
        RECT 110.025 51.305 110.865 51.325 ;
        RECT 110.025 51.005 110.925 51.305 ;
        RECT 110.025 50.505 110.865 50.525 ;
        RECT 110.025 50.205 110.925 50.505 ;
        RECT 109.425 48.605 110.925 48.905 ;
        RECT 105.525 48.205 106.425 48.505 ;
        RECT 108.225 48.205 109.125 48.505 ;
        RECT 105.525 47.705 106.365 47.725 ;
        RECT 108.225 47.705 109.065 47.725 ;
        RECT 105.525 47.405 106.425 47.705 ;
        RECT 108.225 47.405 109.125 47.705 ;
        RECT 109.425 46.905 109.725 48.605 ;
        RECT 111.215 48.105 111.515 60.955 ;
        RECT 110.025 47.805 111.515 48.105 ;
        RECT 104.925 46.605 109.725 46.905 ;
        RECT 103.725 46.205 104.625 46.505 ;
        RECT 110.025 46.205 110.925 46.505 ;
        RECT 82.850 44.360 102.825 45.820 ;
        RECT 105.525 46.105 106.365 46.125 ;
        RECT 108.225 46.105 109.065 46.125 ;
        RECT 105.525 45.805 106.425 46.105 ;
        RECT 108.225 45.805 109.125 46.105 ;
        RECT 109.425 45.905 110.325 46.205 ;
        RECT 105.525 45.305 106.365 45.325 ;
        RECT 108.225 45.305 109.065 45.325 ;
        RECT 105.525 45.005 107.025 45.305 ;
        RECT 108.225 45.005 109.125 45.305 ;
        RECT 103.725 44.905 104.565 44.925 ;
        RECT 103.725 44.605 104.625 44.905 ;
        RECT 106.725 44.505 107.025 45.005 ;
        RECT 108.225 44.505 109.065 44.525 ;
        RECT 109.425 44.505 109.725 45.905 ;
        RECT 110.025 44.605 110.925 44.905 ;
        RECT 82.850 40.190 88.090 44.360 ;
        RECT 89.050 43.790 91.290 44.190 ;
        RECT 88.410 41.790 88.730 42.990 ;
        RECT 89.690 42.190 91.930 42.590 ;
        RECT 92.250 41.790 92.570 42.990 ;
        RECT 89.050 40.590 91.290 40.990 ;
        RECT 82.850 31.820 86.810 40.190 ;
        RECT 87.770 38.320 91.290 38.720 ;
        RECT 87.130 37.120 87.450 38.320 ;
        RECT 88.410 37.520 91.930 37.920 ;
        RECT 92.250 37.120 92.570 38.320 ;
        RECT 87.770 36.720 91.290 37.120 ;
        RECT 87.770 34.540 91.290 34.940 ;
        RECT 87.130 33.340 87.450 34.540 ;
        RECT 88.410 33.740 91.930 34.140 ;
        RECT 92.250 33.340 92.570 34.540 ;
        RECT 87.770 32.940 91.290 33.340 ;
        RECT 92.890 31.820 94.340 44.360 ;
        RECT 95.300 43.790 97.540 44.190 ;
        RECT 94.660 41.790 94.980 42.990 ;
        RECT 95.940 42.190 98.180 42.590 ;
        RECT 98.500 41.790 98.820 42.990 ;
        RECT 99.140 42.505 102.825 44.360 ;
        RECT 105.525 44.205 106.425 44.505 ;
        RECT 106.725 44.205 109.725 44.505 ;
        RECT 103.725 43.805 104.625 44.105 ;
        RECT 110.025 43.805 110.925 44.105 ;
        RECT 105.525 43.705 106.365 43.725 ;
        RECT 108.225 43.705 109.065 43.725 ;
        RECT 105.525 43.405 106.425 43.705 ;
        RECT 108.225 43.405 109.125 43.705 ;
        RECT 105.525 42.905 106.365 42.925 ;
        RECT 108.225 42.905 109.065 42.925 ;
        RECT 104.925 42.605 106.425 42.905 ;
        RECT 108.225 42.605 109.725 42.905 ;
        RECT 104.925 42.505 105.225 42.605 ;
        RECT 99.140 42.205 105.225 42.505 ;
        RECT 99.140 41.355 102.825 42.205 ;
        RECT 104.925 42.105 105.225 42.205 ;
        RECT 109.425 42.505 109.725 42.605 ;
        RECT 111.825 42.505 112.725 61.735 ;
        RECT 109.425 42.205 112.725 42.505 ;
        RECT 105.525 42.105 106.365 42.125 ;
        RECT 108.225 42.105 109.065 42.125 ;
        RECT 109.425 42.105 109.725 42.205 ;
        RECT 104.925 41.805 106.425 42.105 ;
        RECT 108.225 41.805 109.725 42.105 ;
        RECT 111.825 41.355 112.725 42.205 ;
        RECT 95.300 40.590 97.540 40.990 ;
        RECT 99.140 40.680 102.820 41.355 ;
        RECT 99.140 40.190 112.425 40.680 ;
        RECT 100.420 38.720 112.425 40.190 ;
        RECT 95.300 38.320 98.820 38.720 ;
        RECT 94.660 37.120 94.980 38.320 ;
        RECT 95.940 37.520 99.460 37.920 ;
        RECT 99.780 37.120 100.100 38.320 ;
        RECT 95.300 36.720 98.820 37.120 ;
        RECT 95.300 34.540 98.820 34.940 ;
        RECT 94.660 33.340 94.980 34.540 ;
        RECT 95.940 33.740 99.460 34.140 ;
        RECT 99.780 33.340 100.100 34.540 ;
        RECT 100.420 34.065 104.600 38.720 ;
        RECT 105.560 36.845 109.080 37.245 ;
        RECT 104.920 35.645 105.240 36.845 ;
        RECT 106.200 36.045 109.720 36.445 ;
        RECT 110.040 35.645 110.360 36.845 ;
        RECT 105.560 35.245 109.080 35.645 ;
        RECT 110.680 34.065 112.420 38.720 ;
        RECT 95.300 32.940 98.820 33.340 ;
        RECT 100.420 31.820 112.420 34.065 ;
        RECT 82.850 29.990 112.420 31.820 ;
        RECT 82.850 14.070 83.410 29.990 ;
        RECT 84.590 28.030 86.030 29.230 ;
        RECT 85.670 24.430 86.030 28.030 ;
        RECT 86.750 28.030 88.190 29.230 ;
        RECT 86.750 24.430 87.110 28.030 ;
        RECT 87.830 24.430 88.190 28.030 ;
        RECT 88.910 28.030 90.350 29.230 ;
        RECT 88.910 24.430 89.270 28.030 ;
        RECT 89.990 24.430 90.350 28.030 ;
        RECT 91.070 28.030 92.510 29.230 ;
        RECT 91.070 24.430 91.430 28.030 ;
        RECT 92.150 24.430 92.510 28.030 ;
        RECT 93.230 28.030 94.670 29.230 ;
        RECT 93.230 24.430 93.590 28.030 ;
        RECT 94.310 24.430 94.670 28.030 ;
        RECT 95.390 28.030 96.830 29.230 ;
        RECT 95.390 24.430 95.750 28.030 ;
        RECT 96.470 24.430 96.830 28.030 ;
        RECT 97.550 28.030 98.990 29.230 ;
        RECT 97.550 24.430 97.910 28.030 ;
        RECT 98.630 24.430 98.990 28.030 ;
        RECT 99.710 28.030 101.150 29.230 ;
        RECT 99.710 24.430 100.070 28.030 ;
        RECT 100.790 24.430 101.150 28.030 ;
        RECT 101.870 28.030 103.310 29.230 ;
        RECT 101.870 24.430 102.230 28.030 ;
        RECT 85.670 14.830 87.110 17.230 ;
        RECT 87.830 14.830 89.270 17.230 ;
        RECT 89.990 14.830 91.430 17.230 ;
        RECT 92.150 14.830 93.590 17.230 ;
        RECT 94.310 14.830 95.750 17.230 ;
        RECT 96.470 14.830 97.910 17.230 ;
        RECT 98.630 14.830 100.070 17.230 ;
        RECT 100.790 14.830 102.230 17.230 ;
        RECT 104.490 14.070 112.420 29.990 ;
        RECT 82.850 13.530 112.420 14.070 ;
        RECT 82.850 13.510 105.050 13.530 ;
        RECT 43.045 6.910 67.030 8.575 ;
        RECT 43.050 6.525 55.015 6.910 ;
        RECT 55.865 6.525 67.030 6.910 ;
        RECT 43.050 6.000 67.030 6.525 ;
        RECT 110.000 6.000 112.000 13.530 ;
      LAYER met1 ;
        RECT 135.740 108.730 136.100 109.030 ;
        RECT 135.770 108.560 136.070 108.730 ;
        RECT 142.760 108.600 143.120 108.900 ;
        RECT 134.690 108.485 136.090 108.560 ;
        RECT 134.545 108.130 136.090 108.485 ;
        RECT 134.545 108.095 134.995 108.130 ;
        RECT 142.790 108.020 143.090 108.600 ;
        RECT 142.580 106.080 143.460 106.420 ;
        RECT 145.280 106.080 146.160 106.420 ;
        RECT 142.580 105.280 143.460 105.620 ;
        RECT 145.280 105.280 146.160 105.620 ;
        RECT 142.580 104.480 143.460 104.820 ;
        RECT 145.280 104.480 146.160 104.820 ;
        RECT 32.000 101.000 34.000 101.030 ;
        RECT 31.970 99.000 34.030 101.000 ;
        RECT 108.500 99.000 111.000 101.000 ;
        RECT 32.000 98.970 34.000 99.000 ;
        RECT 38.805 94.490 39.685 96.005 ;
        RECT 43.290 95.490 44.170 96.500 ;
        RECT 40.590 93.860 41.470 94.200 ;
        RECT 43.290 93.860 44.170 94.200 ;
        RECT 40.600 92.800 41.400 93.600 ;
        RECT 19.330 72.040 20.350 73.000 ;
        RECT 18.720 64.910 19.040 71.010 ;
        RECT 19.360 64.910 20.320 72.040 ;
        RECT 25.760 70.280 27.215 80.275 ;
        RECT 28.320 74.225 28.640 77.960 ;
        RECT 28.960 74.360 29.920 80.030 ;
        RECT 30.395 73.120 31.595 73.150 ;
        RECT 28.145 72.040 29.165 73.000 ;
        RECT 23.840 64.910 24.800 69.590 ;
        RECT 25.700 68.825 27.275 70.280 ;
        RECT 27.535 64.910 27.855 71.010 ;
        RECT 28.175 64.910 29.135 72.040 ;
        RECT 30.365 71.920 31.625 73.120 ;
        RECT 32.160 73.000 33.120 77.960 ;
        RECT 38.500 74.000 39.500 90.000 ;
        RECT 40.590 89.710 41.470 90.050 ;
        RECT 43.290 89.710 44.170 90.050 ;
        RECT 44.385 77.900 45.345 80.520 ;
        RECT 43.740 74.800 44.060 77.900 ;
        RECT 44.380 76.360 45.345 77.900 ;
        RECT 43.740 74.300 44.065 74.800 ;
        RECT 44.380 74.300 45.340 76.360 ;
        RECT 47.580 75.255 48.540 77.900 ;
        RECT 47.580 74.300 48.545 75.255 ;
        RECT 43.745 73.980 44.065 74.300 ;
        RECT 47.585 73.760 48.545 74.300 ;
        RECT 32.130 72.040 33.150 73.000 ;
        RECT 30.395 71.890 31.595 71.920 ;
        RECT 32.930 70.660 33.310 70.980 ;
        RECT 32.960 69.600 33.280 70.660 ;
        RECT 32.655 64.910 33.615 69.600 ;
        RECT 36.345 64.910 36.665 71.010 ;
        RECT 36.985 64.910 37.945 73.030 ;
        RECT 47.585 72.920 49.550 73.760 ;
        RECT 47.585 72.860 48.545 72.920 ;
        RECT 48.710 72.480 49.550 72.920 ;
        RECT 41.465 64.910 42.425 69.590 ;
        RECT 18.715 61.310 19.040 64.910 ;
        RECT 19.355 61.310 20.320 64.910 ;
        RECT 23.835 61.310 24.800 64.910 ;
        RECT 27.530 61.310 27.855 64.910 ;
        RECT 28.170 61.310 29.135 64.910 ;
        RECT 18.720 60.240 19.040 61.310 ;
        RECT 19.360 60.240 20.320 61.310 ;
        RECT 23.840 60.240 24.800 61.310 ;
        RECT 27.535 60.240 27.855 61.310 ;
        RECT 28.175 60.240 29.135 61.310 ;
        RECT 18.715 56.640 19.040 60.240 ;
        RECT 19.355 56.640 20.320 60.240 ;
        RECT 23.835 56.640 24.800 60.240 ;
        RECT 27.530 56.640 27.855 60.240 ;
        RECT 28.170 56.640 29.135 60.240 ;
        RECT 18.720 55.570 19.040 56.640 ;
        RECT 19.360 55.570 20.320 56.640 ;
        RECT 23.840 55.570 24.800 56.640 ;
        RECT 27.535 55.570 27.855 56.640 ;
        RECT 28.175 55.570 29.135 56.640 ;
        RECT 18.715 52.020 19.040 55.570 ;
        RECT 19.355 53.940 20.320 55.570 ;
        RECT 18.715 51.970 19.035 52.020 ;
        RECT 19.355 51.970 20.315 53.940 ;
        RECT 23.835 51.970 24.800 55.570 ;
        RECT 27.530 52.260 27.855 55.570 ;
        RECT 27.530 51.970 27.850 52.260 ;
        RECT 28.170 51.970 29.135 55.570 ;
        RECT 23.840 50.510 24.800 51.970 ;
        RECT 18.145 49.860 18.525 50.180 ;
        RECT 18.175 45.605 18.495 49.860 ;
        RECT 8.000 15.730 10.000 17.400 ;
        RECT 18.815 17.000 19.775 49.205 ;
        RECT 22.015 44.410 22.975 49.205 ;
        RECT 26.345 45.610 27.305 51.530 ;
        RECT 28.175 51.500 29.135 51.970 ;
        RECT 31.950 60.340 32.435 61.535 ;
        RECT 32.650 61.310 33.615 64.910 ;
        RECT 36.340 61.310 36.665 64.910 ;
        RECT 36.980 61.310 37.945 64.910 ;
        RECT 41.460 61.310 42.425 64.910 ;
        RECT 27.620 47.235 27.955 49.405 ;
        RECT 25.170 43.755 26.130 45.430 ;
        RECT 28.265 44.410 29.225 49.210 ;
        RECT 29.545 45.600 29.865 49.440 ;
        RECT 31.950 45.590 32.290 60.340 ;
        RECT 32.655 60.240 33.615 61.310 ;
        RECT 36.345 60.240 36.665 61.310 ;
        RECT 36.985 60.240 37.945 61.310 ;
        RECT 41.465 60.240 42.425 61.310 ;
        RECT 32.650 56.640 33.615 60.240 ;
        RECT 36.340 56.640 36.665 60.240 ;
        RECT 36.980 56.640 37.945 60.240 ;
        RECT 41.460 56.640 42.425 60.240 ;
        RECT 32.655 55.570 33.615 56.640 ;
        RECT 36.345 55.570 36.665 56.640 ;
        RECT 36.985 55.570 37.945 56.640 ;
        RECT 41.465 55.570 42.425 56.640 ;
        RECT 32.650 51.970 33.615 55.570 ;
        RECT 36.340 51.970 36.665 55.570 ;
        RECT 36.980 52.330 37.945 55.570 ;
        RECT 36.980 51.970 37.940 52.330 ;
        RECT 41.460 51.970 42.425 55.570 ;
        RECT 32.655 50.510 33.615 51.970 ;
        RECT 36.345 51.530 36.665 51.970 ;
        RECT 34.520 51.500 35.480 51.530 ;
        RECT 41.465 51.500 42.425 51.970 ;
        RECT 34.490 50.540 35.510 51.500 ;
        RECT 38.820 50.540 39.840 51.500 ;
        RECT 41.435 50.540 42.455 51.500 ;
        RECT 22.605 42.800 22.925 43.755 ;
        RECT 22.605 34.330 22.930 42.800 ;
        RECT 23.245 41.550 24.205 43.755 ;
        RECT 25.165 42.795 26.130 43.755 ;
        RECT 23.245 40.155 24.210 41.550 ;
        RECT 23.250 39.080 24.210 40.155 ;
        RECT 23.245 35.480 24.210 39.080 ;
        RECT 18.785 16.040 19.805 17.000 ;
        RECT 23.250 16.010 24.210 35.480 ;
        RECT 25.165 36.505 26.125 42.795 ;
        RECT 25.165 33.205 26.130 36.505 ;
        RECT 28.865 34.330 29.185 43.760 ;
        RECT 25.165 32.240 27.230 33.205 ;
        RECT 29.505 16.010 30.465 43.760 ;
        RECT 31.425 35.485 32.385 45.430 ;
        RECT 32.600 44.410 33.560 49.210 ;
        RECT 34.520 45.610 35.480 50.540 ;
        RECT 38.850 48.680 39.810 50.540 ;
        RECT 47.950 50.260 48.270 72.480 ;
        RECT 48.590 68.880 49.550 72.480 ;
        RECT 49.870 70.240 50.830 72.480 ;
        RECT 49.870 69.240 54.230 70.240 ;
        RECT 49.870 68.880 50.830 69.240 ;
        RECT 48.650 67.215 49.490 68.880 ;
        RECT 48.590 63.615 49.550 67.215 ;
        RECT 49.870 64.740 50.830 67.215 ;
        RECT 49.870 63.740 52.730 64.740 ;
        RECT 49.870 63.615 50.830 63.740 ;
        RECT 48.650 62.020 49.490 63.615 ;
        RECT 48.590 58.420 49.550 62.020 ;
        RECT 49.870 58.420 50.830 62.020 ;
        RECT 48.650 56.835 49.490 58.420 ;
        RECT 48.590 53.235 49.550 56.835 ;
        RECT 49.870 56.740 50.830 56.835 ;
        RECT 51.730 56.740 52.730 63.740 ;
        RECT 49.870 55.740 52.730 56.740 ;
        RECT 49.870 53.235 50.830 55.740 ;
        RECT 38.820 47.720 39.840 48.680 ;
        RECT 35.755 35.480 36.715 45.430 ;
        RECT 38.850 44.410 39.810 47.720 ;
        RECT 34.585 33.380 35.845 33.410 ;
        RECT 34.555 32.180 35.875 33.380 ;
        RECT 34.585 32.150 35.845 32.180 ;
        RECT 37.675 17.000 38.635 43.755 ;
        RECT 38.955 34.330 39.275 43.755 ;
        RECT 37.645 16.040 38.665 17.000 ;
        RECT 39.595 16.010 40.555 36.530 ;
        RECT 42.050 16.010 43.010 49.200 ;
        RECT 43.330 45.600 43.650 50.210 ;
        RECT 47.920 49.940 48.300 50.260 ;
        RECT 47.950 49.680 48.270 49.940 ;
        RECT 48.650 49.215 49.490 53.235 ;
        RECT 53.230 51.240 54.230 69.240 ;
        RECT 49.910 50.240 54.230 51.240 ;
        RECT 49.910 48.810 50.910 50.240 ;
        RECT 46.730 47.730 48.275 48.740 ;
        RECT 55.150 34.690 56.590 61.540 ;
        RECT 63.790 60.340 65.230 61.540 ;
        RECT 65.500 53.545 66.500 88.500 ;
        RECT 92.990 87.430 94.190 87.460 ;
        RECT 89.020 86.360 90.040 87.320 ;
        RECT 88.410 74.625 88.730 77.410 ;
        RECT 89.050 77.050 90.010 86.360 ;
        RECT 92.960 86.230 94.220 87.430 ;
        RECT 94.735 86.360 95.755 87.320 ;
        RECT 92.990 86.200 94.190 86.230 ;
        RECT 90.600 84.000 91.300 85.000 ;
        RECT 90.925 81.865 91.245 84.000 ;
        RECT 90.920 81.485 91.245 81.865 ;
        RECT 90.925 81.315 91.245 81.485 ;
        RECT 91.565 79.820 92.525 84.915 ;
        RECT 94.765 81.315 95.725 86.360 ;
        RECT 103.445 81.860 104.465 82.820 ;
        RECT 91.535 78.860 92.555 79.820 ;
        RECT 89.030 76.090 90.050 77.050 ;
        RECT 88.380 74.305 88.760 74.625 ;
        RECT 88.410 73.810 88.730 74.305 ;
        RECT 89.050 73.810 90.010 76.090 ;
        RECT 81.225 56.955 81.545 60.235 ;
        RECT 81.195 56.635 81.575 56.955 ;
        RECT 81.865 56.635 82.825 60.235 ;
        RECT 69.150 55.490 69.650 55.520 ;
        RECT 69.120 54.990 69.680 55.490 ;
        RECT 83.145 55.220 84.105 60.235 ;
        RECT 69.150 54.960 69.650 54.990 ;
        RECT 69.150 54.490 69.650 54.520 ;
        RECT 69.120 53.990 69.680 54.490 ;
        RECT 83.115 54.260 84.135 55.220 ;
        RECT 69.150 53.960 69.650 53.990 ;
        RECT 65.500 53.225 79.625 53.545 ;
        RECT 47.800 34.645 63.800 34.690 ;
        RECT 47.725 31.595 63.800 34.645 ;
        RECT 47.800 31.590 63.800 31.595 ;
        RECT 47.800 28.205 50.900 31.590 ;
        RECT 60.700 28.205 63.800 31.590 ;
        RECT 47.725 25.155 50.900 28.205 ;
        RECT 54.165 25.155 57.215 28.205 ;
        RECT 60.605 25.155 63.800 28.205 ;
        RECT 47.800 21.790 50.900 25.155 ;
        RECT 60.700 21.790 63.800 25.155 ;
        RECT 47.800 21.765 63.800 21.790 ;
        RECT 47.725 18.715 63.800 21.765 ;
        RECT 47.800 18.690 63.800 18.715 ;
        RECT 51.100 13.300 51.500 15.900 ;
        RECT 54.960 8.170 55.920 18.220 ;
        RECT 65.500 15.400 66.500 53.225 ;
        RECT 79.305 49.560 79.625 53.225 ;
        RECT 79.275 49.240 79.655 49.560 ;
        RECT 79.945 48.410 80.905 52.840 ;
        RECT 83.145 49.240 84.105 54.260 ;
        RECT 88.410 52.500 88.730 71.485 ;
        RECT 89.050 71.045 90.010 71.485 ;
        RECT 89.020 70.085 90.040 71.045 ;
        RECT 89.050 61.295 90.010 70.085 ;
        RECT 89.020 60.335 90.040 61.295 ;
        RECT 87.500 51.885 88.730 52.500 ;
        RECT 89.050 51.885 90.010 60.335 ;
        RECT 90.970 51.885 91.930 77.410 ;
        RECT 94.660 73.810 94.980 77.410 ;
        RECT 95.300 77.050 96.260 77.410 ;
        RECT 95.270 76.090 96.290 77.050 ;
        RECT 95.300 73.810 96.260 76.090 ;
        RECT 94.660 64.500 94.980 71.480 ;
        RECT 95.300 71.075 96.260 71.480 ;
        RECT 95.295 70.055 96.260 71.075 ;
        RECT 94.000 63.500 94.980 64.500 ;
        RECT 94.660 58.790 94.980 63.500 ;
        RECT 95.300 61.325 96.260 70.055 ;
        RECT 95.295 60.305 96.260 61.325 ;
        RECT 94.630 58.470 95.010 58.790 ;
        RECT 87.500 51.500 88.700 51.885 ;
        RECT 94.660 51.880 94.980 58.470 ;
        RECT 95.300 53.240 96.260 60.305 ;
        RECT 95.300 52.220 96.270 53.240 ;
        RECT 95.300 51.880 96.260 52.220 ;
        RECT 97.220 51.880 98.180 77.410 ;
        RECT 102.835 64.625 103.155 67.315 ;
        RECT 102.805 64.305 103.185 64.625 ;
        RECT 102.835 63.715 103.155 64.305 ;
        RECT 103.475 63.715 104.435 81.860 ;
        RECT 105.395 63.320 106.355 67.315 ;
        RECT 108.225 64.815 109.105 64.845 ;
        RECT 108.195 63.935 109.135 64.815 ;
        RECT 108.225 63.905 109.105 63.935 ;
        RECT 105.365 62.360 106.385 63.320 ;
        RECT 108.225 60.505 109.105 60.545 ;
        RECT 109.500 60.505 110.500 96.000 ;
        RECT 108.225 60.205 110.500 60.505 ;
        RECT 109.425 60.000 110.500 60.205 ;
        RECT 105.525 59.405 106.405 59.745 ;
        RECT 108.225 59.405 109.105 59.745 ;
        RECT 105.525 58.905 106.405 58.945 ;
        RECT 105.525 58.605 107.025 58.905 ;
        RECT 103.725 58.205 104.605 58.545 ;
        RECT 103.725 56.905 104.605 56.945 ;
        RECT 103.125 56.605 104.605 56.905 ;
        RECT 93.165 51.260 94.125 51.290 ;
        RECT 93.165 50.270 95.135 51.260 ;
        RECT 79.915 47.450 80.935 48.410 ;
        RECT 91.615 46.455 91.935 50.085 ;
        RECT 92.255 45.540 93.215 50.085 ;
        RECT 94.175 46.485 95.135 50.270 ;
        RECT 103.125 49.550 103.425 56.605 ;
        RECT 105.525 56.205 106.405 56.545 ;
        RECT 105.525 55.705 106.405 55.745 ;
        RECT 106.725 55.705 107.025 58.605 ;
        RECT 109.425 57.705 109.725 60.000 ;
        RECT 110.025 57.705 110.905 57.745 ;
        RECT 109.425 57.405 110.905 57.705 ;
        RECT 108.225 57.005 109.105 57.345 ;
        RECT 105.525 55.405 107.025 55.705 ;
        RECT 110.025 55.305 110.905 55.345 ;
        RECT 110.025 55.005 111.525 55.305 ;
        RECT 110.025 54.505 110.905 54.545 ;
        RECT 109.425 54.205 110.905 54.505 ;
        RECT 105.525 53.805 106.405 54.145 ;
        RECT 108.225 53.805 109.105 54.145 ;
        RECT 108.225 53.305 109.105 53.345 ;
        RECT 109.425 53.305 109.725 54.205 ;
        RECT 108.225 53.005 109.725 53.305 ;
        RECT 103.725 52.905 104.605 52.945 ;
        RECT 103.725 52.605 105.225 52.905 ;
        RECT 104.925 51.705 105.225 52.605 ;
        RECT 105.525 52.205 106.405 52.545 ;
        RECT 108.225 52.205 109.105 52.545 ;
        RECT 105.525 51.705 106.405 51.745 ;
        RECT 104.925 51.405 106.405 51.705 ;
        RECT 109.425 50.505 109.725 53.005 ;
        RECT 110.025 51.305 110.905 51.345 ;
        RECT 111.225 51.305 111.525 55.005 ;
        RECT 110.025 51.005 111.525 51.305 ;
        RECT 110.025 50.505 110.905 50.545 ;
        RECT 109.425 50.205 110.905 50.505 ;
        RECT 105.525 49.805 106.405 50.145 ;
        RECT 108.225 49.805 109.105 50.145 ;
        RECT 103.095 49.250 103.455 49.550 ;
        RECT 89.020 44.580 90.040 45.540 ;
        RECT 92.225 44.580 93.245 45.540 ;
        RECT 95.270 44.595 96.290 45.555 ;
        RECT 103.125 44.905 103.425 49.250 ;
        RECT 103.725 48.905 104.605 48.945 ;
        RECT 103.725 48.605 104.625 48.905 ;
        RECT 104.325 48.305 105.225 48.605 ;
        RECT 104.925 45.305 105.225 48.305 ;
        RECT 105.525 47.405 106.405 47.745 ;
        RECT 108.225 47.405 109.105 47.745 ;
        RECT 105.525 45.805 106.405 46.145 ;
        RECT 108.225 45.805 109.105 46.145 ;
        RECT 105.525 45.305 106.405 45.345 ;
        RECT 104.925 45.005 106.405 45.305 ;
        RECT 108.225 45.005 109.105 45.345 ;
        RECT 103.725 44.905 104.605 44.945 ;
        RECT 103.125 44.605 104.605 44.905 ;
        RECT 88.410 44.150 88.730 44.190 ;
        RECT 88.380 43.830 88.760 44.150 ;
        RECT 88.410 43.680 88.730 43.830 ;
        RECT 88.405 43.300 88.730 43.680 ;
        RECT 88.410 40.590 88.730 43.300 ;
        RECT 89.050 40.590 90.010 44.580 ;
        RECT 90.970 44.155 91.930 44.190 ;
        RECT 90.970 43.835 91.965 44.155 ;
        RECT 87.130 36.000 87.450 39.520 ;
        RECT 87.100 35.680 87.480 36.000 ;
        RECT 87.130 32.140 87.450 35.680 ;
        RECT 87.770 31.555 88.730 39.520 ;
        RECT 87.740 30.595 88.760 31.555 ;
        RECT 84.660 29.230 85.860 29.260 ;
        RECT 84.660 28.030 87.995 29.230 ;
        RECT 90.970 29.115 91.930 43.835 ;
        RECT 94.660 40.590 94.980 44.190 ;
        RECT 95.300 40.590 96.260 44.595 ;
        RECT 108.225 44.505 109.105 44.545 ;
        RECT 111.225 44.505 111.525 51.005 ;
        RECT 108.225 44.205 111.525 44.505 ;
        RECT 97.220 41.550 98.180 44.190 ;
        RECT 101.475 44.105 101.775 44.135 ;
        RECT 102.005 44.105 102.305 44.135 ;
        RECT 103.695 44.105 103.995 44.165 ;
        RECT 104.245 44.105 104.545 44.135 ;
        RECT 101.450 43.805 104.545 44.105 ;
        RECT 101.475 43.775 101.775 43.805 ;
        RECT 102.005 43.775 102.305 43.805 ;
        RECT 103.695 43.745 103.995 43.805 ;
        RECT 104.245 43.775 104.545 43.805 ;
        RECT 105.525 43.405 106.405 43.745 ;
        RECT 108.225 43.405 109.105 43.745 ;
        RECT 105.525 42.605 106.405 42.945 ;
        RECT 108.225 42.605 109.105 42.945 ;
        RECT 105.525 41.805 106.405 42.145 ;
        RECT 108.225 41.805 109.105 42.145 ;
        RECT 97.220 40.590 99.490 41.550 ;
        RECT 94.660 36.000 94.980 39.520 ;
        RECT 94.630 35.680 95.010 36.000 ;
        RECT 94.660 32.140 94.980 35.680 ;
        RECT 95.300 31.590 96.260 39.520 ;
        RECT 98.500 32.140 99.460 40.590 ;
        RECT 105.525 40.100 106.405 40.130 ;
        RECT 105.495 39.220 106.435 40.100 ;
        RECT 105.525 39.190 106.405 39.220 ;
        RECT 104.920 36.030 105.240 38.045 ;
        RECT 104.915 35.650 105.240 36.030 ;
        RECT 104.920 34.445 105.240 35.650 ;
        RECT 105.560 33.460 106.520 38.045 ;
        RECT 108.760 34.445 109.720 38.045 ;
        RECT 105.530 32.500 106.550 33.460 ;
        RECT 95.270 30.630 96.290 31.590 ;
        RECT 90.970 28.155 103.200 29.115 ;
        RECT 84.660 28.000 85.860 28.030 ;
        RECT 54.930 7.210 55.950 8.170 ;
        RECT 61.000 8.000 63.000 8.030 ;
        RECT 110.000 8.000 112.000 8.030 ;
        RECT 60.970 6.000 63.030 8.000 ;
        RECT 109.970 6.000 112.030 8.000 ;
        RECT 61.000 5.970 63.000 6.000 ;
        RECT 110.000 5.970 112.000 6.000 ;
      LAYER met2 ;
        RECT 142.800 110.190 143.080 110.225 ;
        RECT 135.780 109.430 136.060 109.465 ;
        RECT 135.770 108.700 136.070 109.430 ;
        RECT 142.790 108.010 143.090 110.190 ;
        RECT 159.320 108.640 160.660 108.860 ;
        RECT 145.280 108.615 160.660 108.640 ;
        RECT 145.260 107.785 160.660 108.615 ;
        RECT 145.280 107.760 160.660 107.785 ;
        RECT 159.320 107.560 160.660 107.760 ;
        RECT 142.580 106.080 143.460 106.420 ;
        RECT 145.280 106.080 146.160 106.420 ;
        RECT 142.580 105.280 143.460 105.620 ;
        RECT 145.280 105.280 146.160 105.620 ;
        RECT 142.580 104.480 143.460 104.820 ;
        RECT 145.280 104.480 146.160 104.820 ;
        RECT 156.710 103.940 158.050 104.130 ;
        RECT 142.580 103.915 158.050 103.940 ;
        RECT 142.560 103.085 158.050 103.915 ;
        RECT 142.580 103.060 158.050 103.085 ;
        RECT 156.710 102.830 158.050 103.060 ;
        RECT 5.500 57.180 7.500 101.000 ;
        RECT 5.500 55.180 7.560 57.180 ;
        RECT 5.500 6.000 7.500 55.180 ;
        RECT 8.000 53.495 10.000 101.000 ;
        RECT 32.000 100.975 34.000 101.030 ;
        RECT 31.980 99.025 34.020 100.975 ;
        RECT 32.000 98.970 34.000 99.025 ;
        RECT 43.290 96.120 44.170 100.465 ;
        RECT 108.500 99.000 111.000 101.000 ;
        RECT 38.805 94.490 39.685 96.005 ;
        RECT 43.270 95.290 44.190 96.120 ;
        RECT 43.290 95.265 44.170 95.290 ;
        RECT 83.000 95.000 110.500 96.000 ;
        RECT 40.590 93.860 41.470 94.200 ;
        RECT 43.290 93.860 44.170 94.200 ;
        RECT 40.600 92.800 41.400 93.600 ;
        RECT 40.590 89.710 41.470 90.050 ;
        RECT 43.290 89.710 44.170 90.050 ;
        RECT 92.960 86.230 94.220 87.430 ;
        RECT 38.500 84.000 91.300 85.000 ;
        RECT 90.895 82.105 91.275 82.425 ;
        RECT 90.925 81.835 91.245 82.105 ;
        RECT 90.890 81.515 91.275 81.835 ;
        RECT 90.920 80.945 91.240 81.515 ;
        RECT 89.060 77.050 90.020 77.080 ;
        RECT 95.300 77.050 96.260 77.080 ;
        RECT 89.060 76.090 96.260 77.050 ;
        RECT 89.060 76.060 90.020 76.090 ;
        RECT 95.300 76.060 96.260 76.090 ;
        RECT 28.320 74.575 28.640 74.580 ;
        RECT 28.290 74.540 28.670 74.575 ;
        RECT 38.500 74.540 39.500 75.000 ;
        RECT 88.410 74.625 88.730 74.655 ;
        RECT 91.460 74.625 91.780 74.655 ;
        RECT 28.290 74.255 44.280 74.540 ;
        RECT 88.410 74.305 95.010 74.625 ;
        RECT 88.410 74.275 88.730 74.305 ;
        RECT 91.460 74.275 91.780 74.305 ;
        RECT 28.320 74.240 44.280 74.255 ;
        RECT 28.320 74.210 28.640 74.240 ;
        RECT 38.500 74.000 39.500 74.240 ;
        RECT 30.365 71.920 31.625 73.120 ;
        RECT 89.050 71.045 90.010 71.075 ;
        RECT 32.960 70.980 33.280 71.010 ;
        RECT 18.690 70.660 27.885 70.980 ;
        RECT 32.960 70.660 36.695 70.980 ;
        RECT 32.960 70.630 33.280 70.660 ;
        RECT 89.050 70.085 96.285 71.045 ;
        RECT 89.050 70.055 90.010 70.085 ;
        RECT 108.250 64.815 109.080 64.835 ;
        RECT 97.305 64.625 97.625 64.655 ;
        RECT 97.770 64.625 98.090 64.655 ;
        RECT 102.835 64.625 103.155 64.655 ;
        RECT 51.800 63.500 95.000 64.500 ;
        RECT 97.235 64.305 103.190 64.625 ;
        RECT 97.305 64.275 97.625 64.305 ;
        RECT 97.770 64.275 98.090 64.305 ;
        RECT 102.835 64.150 103.155 64.305 ;
        RECT 102.805 63.830 103.185 64.150 ;
        RECT 108.195 63.935 109.135 64.815 ;
        RECT 108.250 63.915 109.080 63.935 ;
        RECT 105.395 63.320 106.355 63.350 ;
        RECT 48.650 62.045 49.490 63.040 ;
        RECT 101.420 62.360 106.355 63.320 ;
        RECT 101.420 62.315 102.380 62.360 ;
        RECT 105.395 62.330 106.355 62.360 ;
        RECT 31.940 60.340 65.230 61.540 ;
        RECT 89.050 61.295 90.010 61.325 ;
        RECT 89.050 60.335 96.285 61.295 ;
        RECT 89.050 60.305 90.010 60.335 ;
        RECT 105.525 59.405 106.405 59.745 ;
        RECT 108.225 59.405 109.105 59.745 ;
        RECT 85.725 59.030 86.095 59.350 ;
        RECT 85.730 58.790 86.095 59.030 ;
        RECT 94.660 58.790 94.980 58.820 ;
        RECT 85.645 58.470 94.980 58.790 ;
        RECT 81.955 58.040 82.275 58.070 ;
        RECT 82.450 58.040 82.770 58.070 ;
        RECT 85.695 58.040 86.015 58.470 ;
        RECT 94.660 58.440 94.980 58.470 ;
        RECT 103.725 58.505 104.605 58.545 ;
        RECT 103.725 58.205 105.225 58.505 ;
        RECT 81.955 57.720 86.015 58.040 ;
        RECT 81.955 57.690 82.275 57.720 ;
        RECT 82.450 57.690 82.770 57.720 ;
        RECT 81.225 56.955 81.545 56.985 ;
        RECT 101.540 56.955 101.860 57.000 ;
        RECT 102.005 56.955 102.325 57.000 ;
        RECT 81.225 56.635 102.380 56.955 ;
        RECT 81.225 56.605 81.545 56.635 ;
        RECT 101.540 56.630 101.860 56.635 ;
        RECT 102.005 56.630 102.325 56.635 ;
        RECT 69.175 55.490 69.625 55.510 ;
        RECT 69.120 54.990 69.680 55.490 ;
        RECT 104.925 55.305 105.225 58.205 ;
        RECT 108.225 57.005 109.105 57.345 ;
        RECT 105.525 56.205 106.405 56.545 ;
        RECT 110.025 55.305 110.905 55.345 ;
        RECT 104.925 55.005 110.905 55.305 ;
        RECT 69.175 54.970 69.625 54.990 ;
        RECT 69.175 54.490 69.625 54.510 ;
        RECT 69.120 53.990 69.680 54.490 ;
        RECT 69.175 53.970 69.625 53.990 ;
        RECT 105.525 53.805 106.405 54.145 ;
        RECT 108.225 53.805 109.105 54.145 ;
        RECT 8.000 51.495 10.210 53.495 ;
        RECT 36.345 51.880 36.665 51.885 ;
        RECT 36.315 51.560 36.695 51.880 ;
        RECT 34.520 51.500 35.480 51.530 ;
        RECT 36.345 51.515 36.665 51.560 ;
        RECT 38.850 51.500 39.810 51.530 ;
        RECT 41.465 51.500 42.425 51.530 ;
        RECT 53.300 51.500 88.700 52.500 ;
        RECT 89.000 52.250 96.300 53.210 ;
        RECT 8.000 6.000 10.000 51.495 ;
        RECT 23.810 50.540 27.335 51.500 ;
        RECT 32.625 50.540 35.510 51.500 ;
        RECT 38.850 50.540 42.425 51.500 ;
        RECT 93.160 51.260 94.120 52.250 ;
        RECT 105.525 52.205 106.405 52.545 ;
        RECT 108.225 52.205 109.105 52.545 ;
        RECT 34.520 50.510 35.480 50.540 ;
        RECT 38.850 50.510 39.810 50.540 ;
        RECT 41.465 50.510 42.425 50.540 ;
        RECT 93.135 50.300 94.155 51.260 ;
        RECT 47.950 50.260 48.270 50.290 ;
        RECT 93.160 50.275 94.120 50.300 ;
        RECT 18.175 50.180 18.495 50.210 ;
        RECT 28.340 50.180 28.620 50.205 ;
        RECT 18.175 49.860 43.680 50.180 ;
        RECT 47.905 49.940 48.275 50.260 ;
        RECT 47.950 49.910 48.270 49.940 ;
        RECT 18.175 49.830 18.495 49.860 ;
        RECT 28.340 49.835 28.620 49.860 ;
        RECT 79.275 49.735 79.655 50.055 ;
        RECT 105.525 49.805 106.405 50.145 ;
        RECT 108.225 49.805 109.105 50.145 ;
        RECT 79.305 49.560 79.625 49.735 ;
        RECT 103.125 49.560 103.425 49.580 ;
        RECT 29.530 48.940 55.085 49.440 ;
        RECT 79.305 49.240 103.425 49.560 ;
        RECT 79.305 49.210 79.625 49.240 ;
        RECT 103.125 49.220 103.425 49.240 ;
        RECT 38.850 48.680 39.810 48.710 ;
        RECT 38.850 47.720 39.855 48.680 ;
        RECT 46.730 47.730 48.275 48.740 ;
        RECT 38.850 47.690 39.810 47.720 ;
        RECT 21.985 44.440 26.160 45.400 ;
        RECT 28.235 44.440 33.590 45.400 ;
        RECT 35.725 44.440 39.840 45.400 ;
        RECT 22.575 34.680 23.530 34.685 ;
        RECT 22.575 34.360 39.305 34.680 ;
        RECT 34.585 33.380 35.845 33.425 ;
        RECT 34.555 32.180 35.875 33.380 ;
        RECT 54.585 28.190 55.085 48.940 ;
        RECT 105.525 47.405 106.405 47.745 ;
        RECT 108.225 47.405 109.105 47.745 ;
        RECT 91.585 47.050 91.965 47.370 ;
        RECT 91.615 46.805 91.935 47.050 ;
        RECT 91.585 46.485 91.965 46.805 ;
        RECT 88.410 44.150 88.730 44.180 ;
        RECT 91.615 44.150 91.935 46.485 ;
        RECT 105.525 45.805 106.405 46.145 ;
        RECT 108.225 45.805 109.105 46.145 ;
        RECT 108.225 45.005 109.105 45.345 ;
        RECT 88.405 43.830 95.010 44.150 ;
        RECT 101.475 44.105 101.775 44.150 ;
        RECT 102.005 44.105 102.305 44.150 ;
        RECT 88.405 43.800 88.730 43.830 ;
        RECT 91.615 43.805 91.935 43.830 ;
        RECT 88.405 43.650 88.725 43.800 ;
        RECT 94.660 43.665 94.980 43.830 ;
        RECT 101.445 43.805 101.805 44.105 ;
        RECT 101.975 43.805 102.335 44.105 ;
        RECT 101.475 43.780 101.775 43.805 ;
        RECT 102.005 43.780 102.305 43.805 ;
        RECT 88.375 43.330 88.755 43.650 ;
        RECT 94.630 43.345 95.010 43.665 ;
        RECT 105.525 43.405 106.405 43.745 ;
        RECT 108.225 43.405 109.105 43.745 ;
        RECT 105.525 42.605 106.405 42.945 ;
        RECT 108.225 42.605 109.105 42.945 ;
        RECT 105.525 41.805 106.405 42.145 ;
        RECT 108.225 41.805 109.105 42.145 ;
        RECT 98.500 41.550 99.460 41.580 ;
        RECT 101.415 41.550 102.375 41.595 ;
        RECT 98.500 40.590 102.375 41.550 ;
        RECT 98.500 40.560 99.460 40.590 ;
        RECT 105.550 40.100 106.380 40.120 ;
        RECT 105.495 39.220 106.435 40.100 ;
        RECT 105.550 39.200 106.380 39.220 ;
        RECT 101.445 37.840 102.355 37.860 ;
        RECT 101.420 36.880 109.750 37.840 ;
        RECT 101.445 36.860 102.355 36.880 ;
        RECT 87.130 36.000 87.450 36.030 ;
        RECT 90.940 36.000 91.220 36.025 ;
        RECT 94.660 36.000 94.980 36.030 ;
        RECT 87.130 35.680 105.265 36.000 ;
        RECT 87.130 35.650 87.450 35.680 ;
        RECT 90.940 35.655 91.220 35.680 ;
        RECT 94.660 35.650 94.980 35.680 ;
        RECT 86.765 29.230 87.965 29.260 ;
        RECT 92.990 29.230 94.190 29.275 ;
        RECT 54.200 25.190 57.200 28.190 ;
        RECT 86.765 28.030 94.190 29.230 ;
        RECT 86.765 28.000 87.965 28.030 ;
        RECT 51.100 15.400 66.500 15.900 ;
        RECT 61.000 7.975 63.000 8.030 ;
        RECT 110.000 7.975 112.000 8.030 ;
        RECT 60.980 6.025 63.020 7.975 ;
        RECT 109.980 6.025 112.020 7.975 ;
        RECT 61.000 5.970 63.000 6.025 ;
        RECT 110.000 5.970 112.000 6.025 ;
        RECT 151.000 6.000 153.000 101.000 ;
        RECT 153.500 6.000 155.500 101.000 ;
      LAYER met3 ;
        RECT 142.775 110.190 143.105 110.205 ;
        RECT 131.590 109.890 143.105 110.190 ;
        RECT 50.180 109.410 50.500 109.450 ;
        RECT 131.590 109.410 131.890 109.890 ;
        RECT 142.775 109.875 143.105 109.890 ;
        RECT 50.180 109.110 131.890 109.410 ;
        RECT 135.755 109.430 136.085 109.445 ;
        RECT 136.815 109.430 137.195 109.440 ;
        RECT 138.270 109.430 138.650 109.440 ;
        RECT 135.755 109.130 138.650 109.430 ;
        RECT 135.755 109.115 136.085 109.130 ;
        RECT 136.815 109.120 137.195 109.130 ;
        RECT 138.270 109.120 138.650 109.130 ;
        RECT 50.180 109.070 50.500 109.110 ;
        RECT 83.070 108.770 83.450 108.780 ;
        RECT 94.050 108.770 94.430 108.780 ;
        RECT 83.070 108.470 94.430 108.770 ;
        RECT 83.070 108.460 83.450 108.470 ;
        RECT 94.050 108.460 94.430 108.470 ;
        RECT 136.810 106.300 137.190 106.305 ;
        RECT 38.910 105.985 137.190 106.300 ;
        RECT 38.910 105.980 39.290 105.985 ;
        RECT 142.580 103.060 143.460 107.430 ;
        RECT 145.280 104.230 146.160 108.640 ;
        RECT 159.380 107.580 160.510 108.820 ;
        RECT 156.710 102.760 158.090 104.200 ;
        RECT 5.500 99.000 155.500 101.000 ;
        RECT 5.500 96.500 155.500 98.500 ;
        RECT 38.805 94.490 39.685 96.005 ;
        RECT 40.590 93.610 41.470 96.500 ;
        RECT 40.595 91.060 41.465 93.610 ;
        RECT 40.590 89.460 41.470 91.060 ;
        RECT 43.290 89.460 44.170 96.145 ;
        RECT 83.100 95.650 83.420 95.690 ;
        RECT 84.235 95.650 84.565 95.665 ;
        RECT 83.100 95.350 84.565 95.650 ;
        RECT 83.100 95.310 83.420 95.350 ;
        RECT 84.235 95.335 84.565 95.350 ;
        RECT 70.900 81.545 76.300 86.945 ;
        RECT 78.700 81.545 84.100 86.945 ;
        RECT 73.400 79.145 73.800 81.545 ;
        RECT 81.200 79.145 81.600 81.545 ;
        RECT 90.895 80.965 91.265 81.295 ;
        RECT 28.295 74.230 28.665 74.560 ;
        RECT 70.900 74.245 76.300 79.145 ;
        RECT 78.700 74.245 84.100 79.145 ;
        RECT 85.650 74.245 86.150 74.250 ;
        RECT 5.540 57.180 7.540 57.205 ;
        RECT 1.990 56.955 7.540 57.180 ;
        RECT 0.185 55.405 7.540 56.955 ;
        RECT 1.990 55.180 7.540 55.405 ;
        RECT 5.540 55.155 7.540 55.180 ;
        RECT 8.190 53.495 10.190 53.520 ;
        RECT 2.365 51.495 10.190 53.495 ;
        RECT 8.190 51.470 10.190 51.495 ;
        RECT 16.910 49.260 17.230 50.910 ;
        RECT 28.320 50.185 28.640 74.230 ;
        RECT 70.900 73.745 86.150 74.245 ;
        RECT 28.315 49.855 28.645 50.185 ;
        RECT 16.920 31.180 17.220 49.260 ;
        RECT 30.395 36.120 31.595 73.120 ;
        RECT 70.900 66.240 76.300 71.640 ;
        RECT 78.700 66.240 84.100 71.640 ;
        RECT 73.400 63.840 73.800 66.240 ;
        RECT 81.200 63.840 81.600 66.240 ;
        RECT 48.650 60.640 49.490 63.040 ;
        RECT 46.730 55.240 52.130 60.640 ;
        RECT 70.900 58.940 76.300 63.840 ;
        RECT 78.700 58.940 84.100 63.840 ;
        RECT 85.650 58.940 86.150 73.745 ;
        RECT 70.900 58.440 86.150 58.940 ;
        RECT 69.155 55.490 69.645 55.515 ;
        RECT 69.150 54.990 69.650 55.490 ;
        RECT 69.155 54.965 69.645 54.990 ;
        RECT 69.155 54.490 69.645 54.515 ;
        RECT 69.150 53.990 69.650 54.490 ;
        RECT 69.155 53.965 69.645 53.990 ;
        RECT 36.345 51.865 36.665 51.980 ;
        RECT 36.320 51.535 36.690 51.865 ;
        RECT 70.900 51.830 76.300 57.230 ;
        RECT 78.700 51.830 84.100 57.230 ;
        RECT 36.345 50.530 36.665 51.535 ;
        RECT 44.530 50.560 44.910 50.880 ;
        RECT 38.855 47.695 39.865 48.705 ;
        RECT 30.375 34.920 31.625 36.120 ;
        RECT 34.585 34.920 35.835 36.120 ;
        RECT 34.615 33.405 35.815 34.920 ;
        RECT 34.560 32.205 35.870 33.405 ;
        RECT 44.560 31.340 44.880 50.560 ;
        RECT 47.080 50.260 47.400 50.290 ;
        RECT 47.925 50.260 48.255 50.285 ;
        RECT 47.080 49.940 48.255 50.260 ;
        RECT 47.080 49.910 47.400 49.940 ;
        RECT 47.925 49.915 48.255 49.940 ;
        RECT 73.400 49.430 73.800 51.830 ;
        RECT 81.200 49.430 81.600 51.830 ;
        RECT 46.730 47.730 48.275 48.740 ;
        RECT 70.900 44.530 76.300 49.430 ;
        RECT 78.700 44.530 84.100 49.430 ;
        RECT 85.650 44.530 86.150 58.440 ;
        RECT 70.900 44.030 86.150 44.530 ;
        RECT 90.920 36.005 91.240 80.965 ;
        RECT 90.915 35.675 91.245 36.005 ;
        RECT 10.730 30.680 23.930 31.180 ;
        RECT 10.730 25.780 16.130 30.680 ;
        RECT 18.530 25.780 23.930 30.680 ;
        RECT 38.080 30.840 51.280 31.340 ;
        RECT 38.080 25.940 43.480 30.840 ;
        RECT 45.880 25.940 51.280 30.840 ;
        RECT 92.990 29.255 94.190 87.430 ;
        RECT 153.500 69.460 159.010 69.670 ;
        RECT 153.500 67.880 160.760 69.460 ;
        RECT 153.500 67.670 159.010 67.880 ;
        RECT 101.395 62.335 102.405 63.295 ;
        RECT 101.420 41.575 102.380 62.335 ;
        RECT 101.390 40.615 102.400 41.575 ;
        RECT 101.420 36.880 102.380 40.615 ;
        RECT 105.525 39.220 106.405 60.755 ;
        RECT 108.225 41.555 109.105 64.815 ;
        RECT 151.000 64.115 158.635 66.115 ;
        RECT 92.965 28.055 94.215 29.255 ;
        RECT 13.230 23.380 13.630 25.780 ;
        RECT 21.030 23.380 21.430 25.780 ;
        RECT 40.580 23.540 40.980 25.940 ;
        RECT 48.380 23.540 48.780 25.940 ;
        RECT 10.730 17.980 16.130 23.380 ;
        RECT 18.530 17.980 23.930 23.380 ;
        RECT 38.080 18.140 43.480 23.540 ;
        RECT 45.880 18.140 51.280 23.540 ;
        RECT 5.500 8.500 155.500 10.500 ;
        RECT 5.500 6.000 155.500 8.000 ;
        RECT 2.400 2.400 158.600 4.400 ;
        RECT 0.000 0.000 161.000 2.000 ;
      LAYER met4 ;
        RECT 94.090 110.520 94.150 111.340 ;
        RECT 30.670 109.960 30.970 110.520 ;
        RECT 33.430 109.930 33.730 110.520 ;
        RECT 36.190 109.930 36.490 110.520 ;
        RECT 38.950 110.050 39.250 110.520 ;
        RECT 41.710 109.990 42.010 110.520 ;
        RECT 44.470 109.930 44.770 110.520 ;
        RECT 47.230 109.960 47.530 110.520 ;
        RECT 49.990 110.080 50.290 110.520 ;
        RECT 30.670 109.410 30.970 109.660 ;
        RECT 33.430 109.410 33.730 109.630 ;
        RECT 36.190 109.410 36.490 109.630 ;
        RECT 38.950 109.410 39.250 109.750 ;
        RECT 41.710 109.410 42.010 109.690 ;
        RECT 44.470 109.410 44.770 109.630 ;
        RECT 47.230 109.410 47.530 109.660 ;
        RECT 49.990 109.425 50.290 109.780 ;
        RECT 49.990 109.410 50.505 109.425 ;
        RECT 30.670 109.110 50.670 109.410 ;
        RECT 50.175 109.095 50.505 109.110 ;
        RECT 94.090 108.785 94.390 110.520 ;
        RECT 138.310 109.445 138.610 110.520 ;
        RECT 136.840 109.115 137.170 109.445 ;
        RECT 138.295 109.115 138.625 109.445 ;
        RECT 83.095 108.455 83.425 108.785 ;
        RECT 94.075 108.455 94.405 108.785 ;
        RECT 38.935 105.975 39.265 106.305 ;
        RECT 38.950 96.005 39.250 105.975 ;
        RECT 38.805 94.490 39.685 96.005 ;
        RECT 83.110 95.665 83.410 108.455 ;
        RECT 136.845 106.310 137.160 109.115 ;
        RECT 136.835 105.980 137.165 106.310 ;
        RECT 83.095 95.335 83.425 95.665 ;
        RECT 70.900 81.545 76.300 86.945 ;
        RECT 78.700 81.545 84.100 86.945 ;
        RECT 73.400 79.145 73.800 81.545 ;
        RECT 81.200 79.145 81.600 81.545 ;
        RECT 69.150 74.245 69.650 74.250 ;
        RECT 70.900 74.245 76.300 79.145 ;
        RECT 78.700 74.245 84.100 79.145 ;
        RECT 69.150 73.745 84.100 74.245 ;
        RECT 46.730 55.240 52.130 60.640 ;
        RECT 69.150 58.940 69.650 73.745 ;
        RECT 70.900 66.240 76.300 71.640 ;
        RECT 78.700 66.240 84.100 71.640 ;
        RECT 73.400 63.840 73.800 66.240 ;
        RECT 81.200 63.840 81.600 66.240 ;
        RECT 156.600 66.120 158.600 111.520 ;
        RECT 156.600 64.110 158.610 66.120 ;
        RECT 70.900 58.940 76.300 63.840 ;
        RECT 78.700 58.940 84.100 63.840 ;
        RECT 69.150 58.440 84.100 58.940 ;
        RECT 2.390 51.490 2.400 53.500 ;
        RECT 16.905 50.880 17.235 50.885 ;
        RECT 36.340 50.880 36.670 50.885 ;
        RECT 44.555 50.880 44.885 50.885 ;
        RECT 16.905 50.560 44.885 50.880 ;
        RECT 16.905 50.555 17.235 50.560 ;
        RECT 36.340 50.555 36.670 50.560 ;
        RECT 44.555 50.555 44.885 50.560 ;
        RECT 46.750 48.740 47.710 55.240 ;
        RECT 38.880 48.680 39.840 48.710 ;
        RECT 46.725 48.690 48.275 48.740 ;
        RECT 42.845 48.680 48.275 48.690 ;
        RECT 16.940 47.730 48.275 48.680 ;
        RECT 16.940 47.720 44.900 47.730 ;
        RECT 16.940 31.180 17.900 47.720 ;
        RECT 38.880 47.690 39.840 47.720 ;
        RECT 30.400 36.120 31.600 36.125 ;
        RECT 34.610 36.120 35.810 36.125 ;
        RECT 30.400 34.920 35.810 36.120 ;
        RECT 30.400 34.915 31.600 34.920 ;
        RECT 34.610 34.915 35.810 34.920 ;
        RECT 43.940 31.340 44.900 47.720 ;
        RECT 69.150 44.530 69.650 58.440 ;
        RECT 70.900 51.830 76.300 57.230 ;
        RECT 78.700 51.830 84.100 57.230 ;
        RECT 73.400 49.430 73.800 51.830 ;
        RECT 81.200 49.430 81.600 51.830 ;
        RECT 70.900 44.530 76.300 49.430 ;
        RECT 78.700 44.530 84.100 49.430 ;
        RECT 69.150 44.030 84.100 44.530 ;
        RECT 69.150 44.020 69.650 44.030 ;
        RECT 10.730 30.680 23.930 31.180 ;
        RECT 10.730 25.780 16.130 30.680 ;
        RECT 18.530 25.780 23.930 30.680 ;
        RECT 38.080 30.840 51.280 31.340 ;
        RECT 38.080 25.940 43.480 30.840 ;
        RECT 45.880 25.940 51.280 30.840 ;
        RECT 13.230 23.380 13.630 25.780 ;
        RECT 21.030 23.380 21.430 25.780 ;
        RECT 40.580 23.540 40.980 25.940 ;
        RECT 48.380 23.540 48.780 25.940 ;
        RECT 10.730 17.980 16.130 23.380 ;
        RECT 18.530 17.980 23.930 23.380 ;
        RECT 38.080 18.140 43.480 23.540 ;
        RECT 45.880 18.140 51.280 23.540 ;
        RECT 156.600 0.000 158.600 64.110 ;
        RECT 159.000 0.000 161.000 111.520 ;
  END
END tt_um_lelo_gr02_analogicus
END LIBRARY

